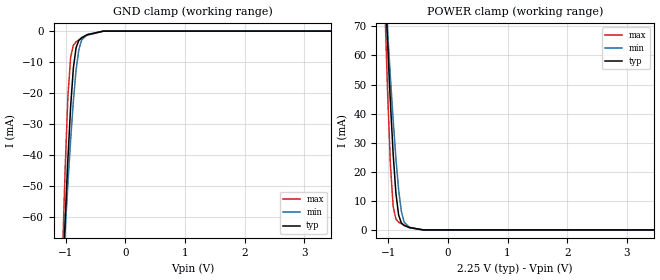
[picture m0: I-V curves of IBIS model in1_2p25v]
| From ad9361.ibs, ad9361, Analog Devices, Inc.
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|   Model: input1_2p25v
[Model]   in1_2p25v
Model_type Input
Vinl=0.45
Vinh=1.8
|   variable   typ   min   max
C_comp   4.040133E-14 3.086166E-14 4.264671E-13
[C Comp Corner]
C_comp   3.086166E-14 4.040133E-14 4.264671E-13
[Temperature Range]   25   85   -40
[Voltage Range]   2.25   2   2.625
[POWER Clamp Reference] 2.25   2   2.625
[GND Clamp Reference]   0   0   0
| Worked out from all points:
|   GND clamp passes 1 mA (typ) near -0.62 V on its own axis
|   POWER clamp passes 1 mA (typ) near -0.67 V on its own axis
[POWER_clamp]
| Voltage   I(typ)   I(min)   I(max)
-2.25V    724.8mA    552.8mA    1.029A
-1.056V   85.22mA    84.31mA    76.21mA
-1.01V    63.87mA    68.14mA    46.81mA
-964.3mV  43.91mA    52.59mA    22.58mA
-918.4mV  26.29mA    37.96mA    8.232mA
-872.4mV  12.74mA    24.76mA    3.764mA
-826.5mV  5.154mA    13.87mA    2.683mA
-780.6mV  2.422mA    6.432mA    2.159mA
-734.7mV  1.55mA     2.726mA    1.717mA
-642.9mV  800uA      772.2uA    924.6uA
-413.3mV  17.51uA    21.54uA    13.88uA
4.5V      -464.6pA   -5.157nA   -72.76pA
[GND_clamp]
| Voltage   I(typ)   I(min)   I(max)
-2.25V    -719.6mA   -548mA     -1.023A
-1.056V   -82.09mA   -80.71mA   -73.35mA
-1.01V    -61.01mA   -64.75mA   -44.48mA
-964.3mV  -41.45mA   -49.48mA   -21.31mA
-918.4mV  -24.46mA   -35.24mA   -8.43mA
-872.4mV  -11.91mA   -22.59mA   -4.569mA
-826.5mV  -5.331mA   -12.5mA    -3.5mA
-780.6mV  -2.988mA   -5.99mA    -2.883mA
-734.7mV  -2.126mA   -2.909mA   -2.337mA
-642.9mV  -1.198mA   -1.119mA   -1.341mA
-367.3mV  -9.539uA   -13.13uA   -5.263uA
4.5V      372pA      1.632nA    55.06pA
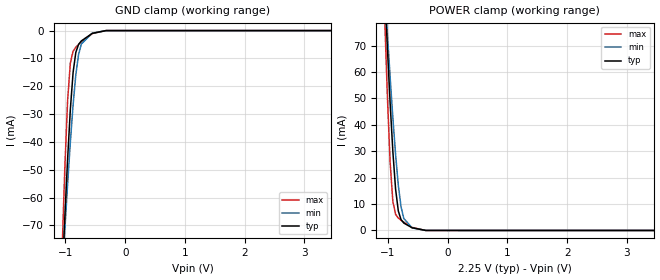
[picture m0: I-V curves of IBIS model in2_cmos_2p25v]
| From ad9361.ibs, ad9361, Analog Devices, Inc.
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|   Model: tx_input_2p25v
[Model]   in2_cmos_2p25v
Model_type Input
Vinl=0.375
Vinh=2.125
|   variable   typ   min   max
C_comp_power_clamp 9.285036E-13 8.725727E-13 1.103895E-12
C_comp_gnd_clamp   5.374554E-13 4.573817e-13 5.723049E-13
[C Comp Corner]
C_comp_power_clamp 9.285036E-13 1.103895E-12 8.725727E-13
C_comp_gnd_clamp   4.573817e-13 5.374554E-13 5.723049E-13
[Temperature Range]   25   85   -40
[Voltage Range]   2.25   2   2.625
[Power Clamp Reference]  2.25   2   2.625
[GND Clamp Reference]   0   0   0
[Pullup Reference]   2.25   2   2.625
[Pulldown Reference]   0   0   0
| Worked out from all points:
|   GND clamp passes 1 mA (typ) near -0.55 V on its own axis
|   POWER clamp passes 1 mA (typ) near -0.59 V on its own axis
[POWER_clamp]
| Voltage   I(typ)   I(min)   I(max)
-2.25V    758.5mA    585mA      1.064A
-1.056V   91.6mA     91.71mA    81.27mA
-1.01V    69.31mA    74.66mA    50.95mA
-964.3mV  48.45mA    58.25mA    25.93mA
-918.4mV  29.96mA    42.77mA    11mA
-872.4mV  15.62mA    28.75mA    6.12mA
-826.5mV  7.344mA    17.08mA    4.702mA
-780.6mV  4.069mA    8.909mA    3.864mA
-734.7mV  2.808mA    4.54mA     3.121mA
-596.9mV  1.035mA    991.2uA    1.17mA
-367.3mV  12.51uA    16.97uA    8.336uA
4.5V      -2.684nA   -19.17nA   -199.2pA
[GND_clamp]
| Voltage   I(typ)   I(min)   I(max)
-2.25V    -753.4mA   -580.1mA   -1.059A
-1.056V   -88.67mA   -88.22mA   -78.71mA
-1.01V    -66.66mA   -71.38mA   -48.96mA
-964.3mV  -46.19mA   -55.25mA   -25.09mA
-918.4mV  -28.35mA   -40.16mA   -11.69mA
-872.4mV  -15.03mA   -26.7mA    -7.416mA
-826.5mV  -7.805mA   -15.83mA   -5.976mA
-780.6mV  -4.962mA   -8.594mA   -5.001mA
-734.7mV  -3.72mA    -4.864mA   -4.107mA
-551mV    -1.001mA   -916.1uA   -1.063mA
-321.4mV  -5.147uA   -8.309uA   -2.147uA
4.5V      2.413nA    17.88nA    77.97pA
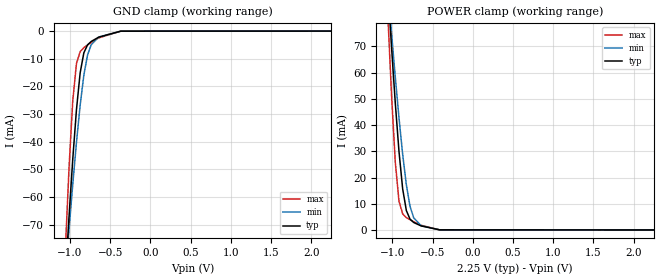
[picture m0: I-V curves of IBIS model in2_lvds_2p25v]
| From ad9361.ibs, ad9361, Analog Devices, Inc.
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|   Model: tx_input_2p25v
[Model]   in2_lvds_2p25v
Model_type Input
Vinl=0.375
Vinh=2.125
|   variable   typ   min   max
C_comp   5.374554E-13 4.573817e-13 5.723049E-13
[C Comp Corner]
C_comp   4.573817e-13 5.374554E-13 5.723049E-13
|C_comp_gnd_clamp 7.430165e-13 8.246844e-13 7.442808e-13
|C_comp_power_clamp 1.550972e-12 1.788704e-12 1.474126e-12
[Temperature Range]   25   85   -40
[Voltage Range]   2.25   2   2.625
[Power Clamp Reference]  2.25   2   2.625
[GND Clamp Reference]   0   0   0
[Pullup Reference]   2.25   2   2.625
[Pulldown Reference]   0   0   0
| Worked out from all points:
|   GND clamp passes 1 mA (typ) near -0.55 V on its own axis
|   POWER clamp passes 1 mA (typ) near -0.59 V on its own axis
[POWER_clamp]
| Voltage   I(typ)   I(min)   I(max)
-2.25V    758.6mA    585.1mA    1.064A
-1.056V   91.68mA    91.83mA    81.33mA
-1.01V    69.39mA    74.78mA    50.99mA
-964.3mV  48.52mA    58.36mA    25.97mA
-918.4mV  30.03mA    42.87mA    11.03mA
-872.4mV  15.67mA    28.85mA    6.146mA
-826.5mV  7.389mA    17.17mA    4.727mA
-780.6mV  4.105mA    8.984mA    3.889mA
-734.7mV  2.836mA    4.602mA    3.144mA
-642.9mV  1.544mA    1.62mA     1.781mA
-413.3mV  46.7uA     54.09uA    39.39uA
2.25V     -312.9pA   -1.046uA   -50.19pA
[GND_clamp]
| Voltage   I(typ)   I(min)   I(max)
-2.25V    -753.5mA   -580.2mA   -1.059A
-1.056V   -88.74mA   -88.33mA   -78.75mA
-1.01V    -66.72mA   -71.49mA   -48.99mA
-964.3mV  -46.25mA   -55.35mA   -25.11mA
-918.4mV  -28.4mA    -40.25mA   -11.71mA
-872.4mV  -15.08mA   -26.79mA   -7.437mA
-826.5mV  -7.843mA   -15.9mA    -5.998mA
-780.6mV  -4.993mA   -8.663mA   -5.023mA
-734.7mV  -3.748mA   -4.922mA   -4.129mA
-642.9mV  -2.214mA   -2.151mA   -2.472mA
-367.3mV  -25.76uA   -33.23uA   -15.79uA
2.25V     246.3pA    667.5nA    45.92pA
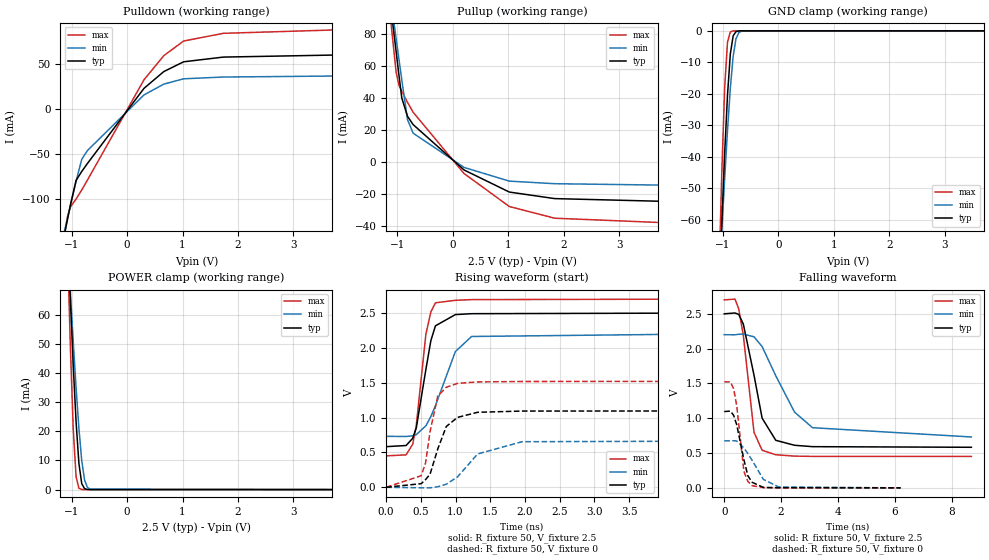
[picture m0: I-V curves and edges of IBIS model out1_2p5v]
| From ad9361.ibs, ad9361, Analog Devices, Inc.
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|   Model: output1_2p5v
[Model]   out1_2p5v
Model_type  3-state
Vref=0
Vmeas=1.125
Rref=1G
Cref=3pF
|variable   typ   min   max
C_comp_pullup   3.786304E-13 3.343610E-13 3.932215E-13
C_comp_pulldown   3.175618E-13 2.997974E-13 4.121601E-13
[C Comp Corner]
C_comp_pullup   3.343610E-13 3.932215E-13 3.786304E-13
C_comp_pulldown   2.997974E-13 4.121601E-13 3.175618E-13
[Temperature Range]   25   85   -40
[Voltage Range]   2.5   2.2   2.7
[Power Clamp Reference] 2.5   2.2   2.7
[GND Clamp Reference]   0   0   0
[Pullup Reference]   2.5   2.2   2.7
[Pulldown Reference]   0   0   0
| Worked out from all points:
|   slope of the pulldown table from 0 to 0.375 V, typ, clamps not added: 13.7 ohm
|   slope of the pullup table from 0 to 0.375 V, typ, clamps not added: 41.8 ohm
|   GND clamp passes 1 mA (typ) near -0.79 V on its own axis
|   POWER clamp passes 1 mA (typ) near -0.79 V on its own axis
|   rising waveform, R_fixture 50, V_fixture 2.5: 20-80 % time 186ps typ, 328ps min, 148ps max; typ from 0.583 V to 2.5 V
|   falling waveform, R_fixture 50, V_fixture 2.5: 20-80 % time 530ps typ, 1.11ns min, 365ps max; typ from 2.5 V to 0.583 V
|   rising waveform, R_fixture 50, V_fixture 0: 20-80 % time 226ps typ, 425ps min, 159ps max; typ from 0 V to 1.1 V
|   falling waveform, R_fixture 50, V_fixture 0: 20-80 % time 339ps typ, 598ps min, 246ps max; typ from 1.1 V to 0 V
[Power clamp]
| Voltage   I(typ)   I(min)   I(max)
-2.5V     835.1mA    627.7mA    1.205A
-1.071V   87.93mA    84.9mA     81.41mA
-1.02V    64.48mA    67.45mA    48.31mA
-969.4mV  42.54mA    50.69mA    20.66mA
-918.4mV  23.27mA    34.97mA    4.431mA
-867.3mV  8.965mA    20.98mA    449.5uA
-816.3mV  2.046mA    9.914mA    36.63uA
-765.3mV  322uA      3.267mA    2.917uA
-714.3mV  45.7uA     765.8uA    231.8nA
-663.3mV  6.378uA    153.6uA    18.42nA
5V        -10pA      -10.07pA   -10pA
[GND Clamp]
| Voltage   I(typ)   I(min)   I(max)
-2.5V     -829.5mA   -622.5mA   -1.199A
-1.071V   -83.56mA   -80.69mA   -77.03mA
-1.02V    -60.42mA   -63.43mA   -44.54mA
-969.4mV  -38.93mA   -46.93mA   -18.07mA
-918.4mV  -20.43mA   -31.61mA   -3.595mA
-867.3mV  -7.361mA   -18.23mA   -364.6uA
-816.3mV  -1.595mA   -8.11mA    -31.06uA
-765.3mV  -253.4uA   -2.511mA   -2.598uA
-714.3mV  -37.22uA   -578.3uA   -217nA
-663.3mV  -5.395uA   -118.2uA   -18.12nA
5V        10pA       9.933pA    10pA
[Pullup]
| Voltage   I(typ)   I(min)   I(max)
-2.5V     493.3mA    449.2mA    559.2mA
-1.122V   98.28mA    102.8mA    90.27mA
-1.071V   83.57mA    89.97mA    72.81mA
-1.02V    68.84mA    77.1mA     55.94mA
-969.4mV  54.11mA    64.2mA     47.85mA
-918.4mV  39.94mA    51.26mA    44.22mA
-816.3mV  28.52mA    26.5mA     37.24mA
-714.3mV  23.26mA    17.89mA    30.99mA
204.1mV   -5.177mA   -3.583mA   -7.408mA
1.02V     -19.01mA   -12.17mA   -28.07mA
1.837V    -23.11mA   -13.78mA   -35.39mA
5V        -25.88mA   -15.21mA   -39.9mA
[Pulldown]
| Voltage   I(typ)   I(min)   I(max)
-2.5V     -546.8mA   -489.9mA   -626.1mA
-1.122V   -138.1mA   -134.6mA   -137.9mA
-1.071V   -122.5mA   -121.1mA   -119.5mA
-1.02V    -106.9mA   -107.6mA   -109.2mA
-918.4mV  -79.64mA   -80.52mA   -100.4mA
-816.3mV  -69.62mA   -56.09mA   -90.25mA
-714.3mV  -60.77mA   -46.31mA   -79.29mA
306.1mV   23.11mA    15.79mA    32.66mA
663.3mV   41.82mA    27.81mA    59.6mA
1.02V     52.7mA     33.75mA    75.87mA
1.735V    57.95mA    35.71mA    84.45mA
5V        61.68mA    37.52mA    90.61mA
[Rising Waveform]
R_fixture = 50
V_fixture = 2.5
V_fixture_min = 2.2
V_fixture_max = 2.7
| time   V(typ)   V(min)   V(max)
0s        583mV      731.1mV    451.1mV
287.2ps   599.6mV    729mV      465.2mV
382ps     702.8mV    738.9mV    617.3mV
433.9ps   851.7mV    755.5mV    890.2mV
572.6ps   1.694V     882.9mV    2.199V
643.8ps   2.104V     1.015V     2.516V
710.1ps   2.317V     1.172V     2.647V
996.5ps   2.478V     1.947V     2.683V
1.231ns   2.491V     2.164V     2.693V
4.552ns   2.5V       2.2V       2.7V
[Falling Waveform]
R_fixture = 50
V_fixture = 2.5
V_fixture_min = 2.2
V_fixture_max = 2.7
| time   V(typ)   V(min)   V(max)
0s        2.5V       2.2V       2.7V
378ps     2.512V     2.199V     2.711V
510.3ps   2.492V     2.206V     2.571V
672.2ps   2.352V     2.209V     2.189V
1.048ns   1.617V     2.17V      797.2mV
1.333ns   1.001V     2.029V     539.6mV
1.813ns   682.9mV    1.61V      475.7mV
2.473ns   611.7mV    1.088V     455.9mV
3.105ns   591.8mV    864.1mV    451.9mV
8.693ns   582.9mV    731mV      451.1mV
[Rising Waveform]
R_fixture = 50
V_fixture = 0
V_fixture_min = 0
V_fixture_max = 0
| time   V(typ)   V(min)   V(max)
0s        19.37uV    15.21uV    23.25uV
504.8ps   52.06mV    -7.305mV   165.8mV
567.9ps   110.5mV    -8.171mV   350.6mV
632.5ps   188.6mV    -7.654mV   800.1mV
742.5ps   547.3mV    7.585mV    1.308V
865.9ps   872.2mV    44.05mV    1.435V
1.027ns   1.003V     148mV      1.491V
1.317ns   1.076V     478.2mV    1.512V
1.958ns   1.094V     654.1mV    1.518V
9.544ns   1.096V     674.9mV    1.523V
[Falling Waveform]
R_fixture = 50
V_fixture = 0
V_fixture_min = 0
V_fixture_max = 0
| time   V(typ)   V(min)   V(max)
0s        1.096V     674.9mV    1.523V
218.4ps   1.103V     675.9mV    1.523V
334.3ps   1.039V     677.5mV    1.42V
441.1ps   903.1mV    673mV      1.174V
692.4ps   404.6mV    572.7mV    237mV
831.1ps   173.9mV    492.8mV    93.71mV
982.1ps   80mV       395.5mV    31.05mV
1.375ns   5.95mV     122mV      4.401mV
1.912ns   1.701mV    13.25mV    958.5uV
6.204ns   -9.734uV   432.3nV    -2.344uV
[Ramp]
| variable   typ   min   max
dV/dt_r  0.657452/2.26E-10   0.404945/4.25E-10   0.913694/1.59E-10
dV/dt_f  1.150229/5.3E-10   0.881349/1.11E-09   1.349344/3.65E-10
R_load = 50
|   End of [Model]: output1_2p5v
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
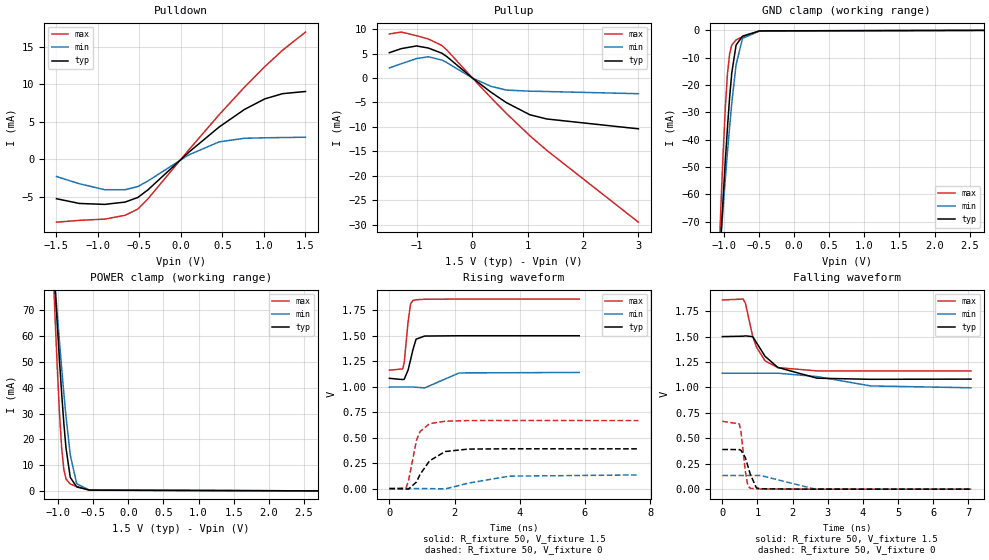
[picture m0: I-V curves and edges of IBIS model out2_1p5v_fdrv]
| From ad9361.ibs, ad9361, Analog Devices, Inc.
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|   Model: output1_1p5v_fdrv
[Model]   out2_1p5v_fdrv
Model_type  3-state
Vref=0
Vmeas=0.75
Rref=1G
Cref=3pF
|variable   typ   min   max
C_comp_pullup   2.194652E-14 1.815507E-14 2.472456E-13
C_comp_pulldown   7.095162E-14   7.061154E-14   9.191828E-14
[C Comp Corner]
C_comp_pullup   2.194652E-14 1.815507E-14 2.472456E-13
C_comp_pulldown   7.061154E-14  7.095162E-14   9.191828E-14
[Temperature Range]   25   85   -40
[Voltage Range]   1.5   1.14   1.86
[Power Clamp Reference] 1.5   1.14   1.86
[GND Clamp Reference]   0   0   0
[Pullup Reference]   1.5   1.14   1.86
[Pulldown Reference]   0   0   0
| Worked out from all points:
|   slope of the pulldown table from 0 to 0.225 V, typ, clamps not added: 102 ohm
|   slope of the pullup table from 0 to 0.225 V, typ, clamps not added: 114 ohm
|   GND clamp passes 1 mA (typ) near -0.62 V on its own axis
|   POWER clamp passes 1 mA (typ) near -0.67 V on its own axis
|   rising waveform, R_fixture 50, V_fixture 1.5: 20-80 % time 195ps typ, 390ps min, 134ps max; typ from 1.08 V to 1.5 V
|   falling waveform, R_fixture 50, V_fixture 1.5: 20-80 % time 739ps typ, 1.16ns min, 412ps max; typ from 1.5 V to 1.08 V
|   rising waveform, R_fixture 50, V_fixture 0: 20-80 % time 530ps typ, 1.06ns min, 295ps max; typ from 0 V to 0.39 V
|   falling waveform, R_fixture 50, V_fixture 0: 20-80 % time 202ps typ, 456ps min, 135ps max; typ from 0.39 V to 0 V
[Power clamp]
| Voltage   I(typ)   I(min)   I(max)
-1.5V     315.2mA    253.3mA    416.6mA
-1.071V   92.57mA    89.81mA    86.68mA
-1.041V   78mA       78.87mA    66.08mA
-1.01V    63.89mA    68.15mA    46.88mA
-979.6mV  50.39mA    57.71mA    29.94mA
-949mV    37.76mA    47.61mA    16.67mA
-918.4mV  26.36mA    37.99mA    8.422mA
-887.8mV  16.76mA    28.99mA    4.656mA
-826.5mV  5.248mA    13.94mA    2.684mA
-734.7mV  1.554mA    2.767mA    1.717mA
-551mV    302.9uA    280.6uA    313uA
3V        -277.9pA   -2.353nA   -34.9pA
[GND Clamp]
| Voltage   I(typ)   I(min)   I(max)
-1.5V     -310.6mA   -248.8mA   -412.2mA
-1.071V   -89.35mA   -86.15mA   -83.72mA
-1.041V   -74.95mA   -75.34mA   -63.36mA
-1.01V    -61.03mA   -64.76mA   -44.55mA
-979.6mV  -47.78mA   -54.49mA   -28.26mA
-949mV    -35.47mA   -44.62mA   -15.91mA
-918.4mV  -24.54mA   -35.26mA   -8.594mA
-887.8mV  -15.57mA   -26.62mA   -5.351mA
-826.5mV  -5.408mA   -12.57mA   -3.501mA
-734.7mV  -2.129mA   -2.939mA   -2.338mA
-489.8mV  -207.4uA   -201.8uA   -188.8uA
3V        251.7pA    4.602nA    34.07pA
[Pullup]
| Voltage   I(typ)   I(min)   I(max)
-1.5V     5.172mA    2.057mA    9mA
-1.286V   5.99mA     2.909mA    9.378mA
-1.01V    6.55mA     3.968mA    8.65mA
-795.9mV  6.117mA    4.337mA    7.962mA
-551mV    5.057mA    3.651mA    6.634mA
-459.2mV  4.342mA    3.119mA    5.685mA
0V        260.8nA    540.6nA    125.1nA
336.7mV   -2.914mA   -1.708mA   -4.047mA
612.2mV   -5.021mA   -2.471mA   -7.22mA
1.041V    -7.528mA   -2.695mA   -11.83mA
1.347V    -8.381mA   -2.767mA   -14.81mA
3V        -10.39mA   -3.213mA   -29.47mA
[Pulldown]
| Voltage   I(typ)   I(min)   I(max)
-1.5V     -5.271mA   -2.307mA   -8.404mA
-1.224V   -5.903mA   -3.272mA   -8.157mA
-918.4mV  -6.027mA   -4.068mA   -7.995mA
-673.5mV  -5.719mA   -4.067mA   -7.483mA
-520.4mV  -5.107mA   -3.65mA    -6.653mA
-398mV    -4.082mA   -2.898mA   -5.286mA
91.84mV   916.9uA    574.5uA    1.22mA
459.2mV   4.302mA    2.32mA     5.941mA
765.3mV   6.653mA    2.803mA    9.632mA
1.01V     8.063mA    2.868mA    12.37mA
1.224V    8.758mA    2.9mA      14.56mA
1.5V      9.049mA    2.936mA    16.98mA
[Rising Waveform]
R_fixture = 50
V_fixture = 1.5
V_fixture_min = 1.14
V_fixture_max = 1.86
| time   V(typ)   V(min)   V(max)
0s        1.082V     996.7mV    1.162V
409.4ps   1.07V      996.7mV    1.175V
452.3ps   1.072V     996.7mV    1.23V
574ps     1.163V     996.8mV    1.636V
650.7ps   1.265V     997mV      1.813V
723.4ps   1.364V     997.1mV    1.846V
818ps     1.466V     994.8mV    1.853V
1.079ns   1.497V     987.7mV    1.858V
2.144ns   1.5V       1.135V     1.86V
5.825ns   1.5V       1.14V      1.86V
[Falling Waveform]
R_fixture = 50
V_fixture = 1.5
V_fixture_min = 1.14
V_fixture_max = 1.86
| time   V(typ)   V(min)   V(max)
0s        1.5V       1.14V      1.86V
593.3ps   1.504V     1.14V      1.869V
657.5ps   1.507V     1.14V      1.828V
867ps     1.499V     1.14V      1.499V
974ps     1.44V      1.14V      1.397V
1.215ns   1.307V     1.14V      1.262V
1.58ns    1.197V     1.14V      1.195V
2.694ns   1.091V     1.107V     1.163V
4.219ns   1.08V      1.015V     1.162V
7.076ns   1.082V     996.8mV    1.162V
[Rising Waveform]
R_fixture = 50
V_fixture = 0
V_fixture_min = 0
V_fixture_max = 0
| time   V(typ)   V(min)   V(max)
0s        -1.048nV   8.167nV    -604.6pV
510.7ps   -3.493mV   1.253uV    7.752mV
582.4ps   -5.65mV    -5.414uV   71.56mV
832ps     64.81mV    94.02uV    474mV
940.3ps   138.5mV    197uV      559.7mV
1.233ns   272.3mV    -379.6uV   637.4mV
1.712ns   363.6mV    -3.085mV   661.2mV
2.417ns   387.8mV    53.18mV    667.5mV
3.683ns   390.5mV    122.2mV    667.8mV
7.642ns   390.1mV    134.2mV    667.4mV
[Falling Waveform]
R_fixture = 50
V_fixture = 0
V_fixture_min = 0
V_fixture_max = 0
| time   V(typ)   V(min)   V(max)
0s        390.1mV    134.2mV    667.5mV
485ps     389.2mV    134.2mV    641.6mV
532.9ps   381mV      134.2mV    559.8mV
654.5ps   311.1mV    134.2mV    176.6mV
726.9ps   228.1mV    134.2mV    34.37mV
797ps     145.7mV    134.2mV    8.667mV
969.8ps   13.38mV    134.2mV    3.326mV
1.089ns   3.278mV    134.8mV    1.45mV
2.606ns   70.89uV    3.36mV     15.67uV
7.084ns   175.1nV    1.547uV    1.93uV
[Ramp]
| variable   typ   min   max
dV/dt_r  0.250830/7.38E-10   0.086493/1.19E-10   0.418507/4.12E-10
dV/dt_f  0.234081/5.30E-10   0.080509/1.06E-10   0.400463/2.95E-10
R_load = 50
|   End of [Model]: output1_1p5v_fdrv
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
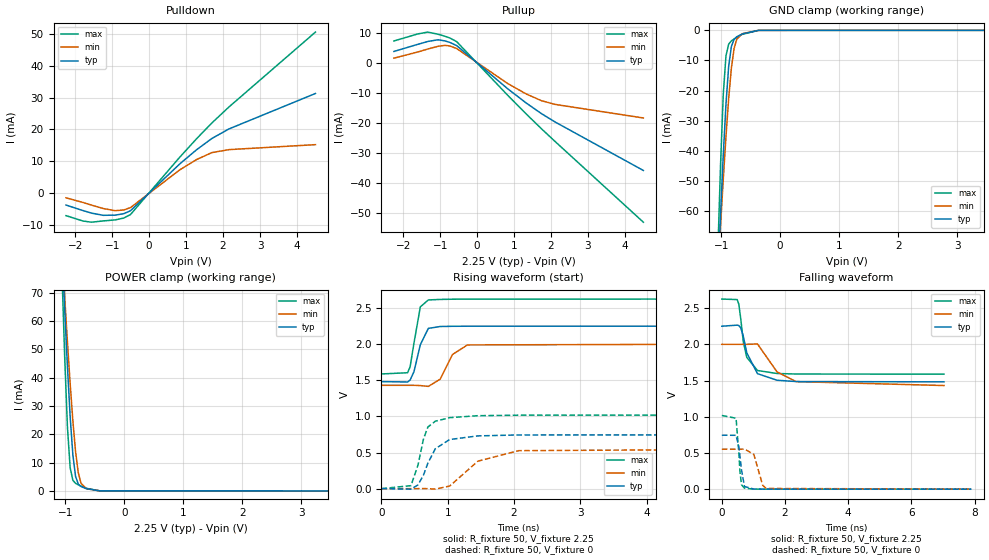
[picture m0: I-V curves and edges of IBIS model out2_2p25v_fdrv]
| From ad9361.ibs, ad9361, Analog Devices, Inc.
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|   Model: output1_2p25v_fdrv
[Model]   out2_2p25v_fdrv
Model_type  3-state
Vref=0
Vmeas=1.125
Rref=1G
Cref=3pF
|variable   typ   min   max
C_comp_pullup   3.897946E-14 8.455150E-15 2.538428E-13
C_comp_pulldown   9.928410E-14 9.028872E-14  1.727192E-13
[C Comp Corner]
C_comp_pullup   8.455150E-15 3.897946E-14 2.538428E-13
C_comp_pulldown   9.928410E-14  9.028872E-14 1.727192E-13
[Temperature Range]   25   85   -40
[Voltage Range]   2.25   2   2.625
[Power Clamp Reference]  2.25   2   2.625
[GND Clamp Reference]   0   0   0
[Pullup Reference]   2.25   2   2.625
[Pulldown Reference]   0   0   0
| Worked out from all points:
|   slope of the pulldown table from 0 to 0.337 V, typ, clamps not added: 88 ohm
|   slope of the pullup table from 0 to 0.337 V, typ, clamps not added: 93.9 ohm
|   GND clamp passes 1 mA (typ) near -0.62 V on its own axis
|   POWER clamp passes 1 mA (typ) near -0.67 V on its own axis
|   rising waveform, R_fixture 50, V_fixture 2.25: 20-80 % time 119ps typ, 198ps min, 110ps max; typ from 1.48 V to 2.25 V
|   falling waveform, R_fixture 50, V_fixture 2.25: 20-80 % time 357ps typ, 679ps min, 227ps max; typ from 2.25 V to 1.48 V
|   rising waveform, R_fixture 50, V_fixture 0: 20-80 % time 245ps typ, 476ps min, 167ps max; typ from 0 V to 0.745 V
|   falling waveform, R_fixture 50, V_fixture 0: 20-80 % time 118ps typ, 212ps min, 92.3ps max; typ from 0.745 V to 0 V
[Power clamp]
| Voltage   I(typ)   I(min)   I(max)
-2.25V    724.8mA    552.8mA    1.029A
-1.056V   85.22mA    84.31mA    76.21mA
-1.01V    63.87mA    68.14mA    46.81mA
-964.3mV  43.91mA    52.59mA    22.58mA
-918.4mV  26.29mA    37.96mA    8.232mA
-872.4mV  12.74mA    24.76mA    3.764mA
-826.5mV  5.154mA    13.87mA    2.683mA
-780.6mV  2.422mA    6.432mA    2.159mA
-734.7mV  1.55mA     2.726mA    1.717mA
-642.9mV  800uA      772.2uA    924.6uA
-413.3mV  17.51uA    21.54uA    13.88uA
4.5V      -464.6pA   -5.157nA   -72.76pA
[GND Clamp]
| Voltage   I(typ)   I(min)   I(max)
-2.25V    -719.6mA   -548mA     -1.023A
-1.056V   -82.09mA   -80.71mA   -73.35mA
-1.01V    -61.01mA   -64.75mA   -44.48mA
-964.3mV  -41.45mA   -49.48mA   -21.31mA
-918.4mV  -24.46mA   -35.24mA   -8.43mA
-872.4mV  -11.91mA   -22.59mA   -4.569mA
-826.5mV  -5.331mA   -12.5mA    -3.5mA
-780.6mV  -2.988mA   -5.99mA    -2.883mA
-734.7mV  -2.126mA   -2.909mA   -2.337mA
-642.9mV  -1.198mA   -1.119mA   -1.341mA
-367.3mV  -9.539uA   -13.13uA   -5.263uA
4.5V      372pA      1.632nA    55.06pA
[Pullup]
| Voltage   I(typ)   I(min)   I(max)
-2.25V    3.851mA    1.612mA    7.34mA
-1.607V   6.212mA    3.658mA    9.69mA
-1.332V   7.182mA    4.662mA    10.31mA
-1.056V   7.739mA    5.563mA    9.593mA
-872.4mV  7.384mA    5.88mA     8.936mA
-734.7mV  6.851mA    5.68mA     8.325mA
-551mV    5.811mA    4.813mA    7.12mA
826.5mV   -8.58mA    -6.839mA   -10.74mA
1.332V    -13.37mA   -10.35mA   -17.03mA
1.745V    -16.92mA   -12.59mA   -21.98mA
2.112V    -19.69mA   -13.82mA   -26.2mA
4.5V      -35.86mA   -18.35mA   -53.12mA
[Pulldown]
| Voltage   I(typ)   I(min)   I(max)
-2.25V    -3.829mA   -1.549mA   -7.157mA
-1.791V   -5.567mA   -3.018mA   -8.856mA
-1.561V   -6.363mA   -3.838mA   -9.223mA
-1.24V    -7.063mA   -4.932mA   -8.817mA
-918.4mV  -7.002mA   -5.597mA   -8.502mA
-688.8mV  -6.544mA   -5.384mA   -7.927mA
-505.1mV  -5.626mA   -4.635mA   -6.816mA
826.5mV   9.098mA    7.231mA    11.21mA
1.286V    13.6mA     10.51mA    17.07mA
1.699V    17.13mA    12.68mA    22.02mA
2.158V    20.12mA    13.61mA    27.02mA
4.5V      31.28mA    15.18mA    50.6mA
[Rising Waveform]
R_fixture = 50
V_fixture = 2.25
V_fixture_min = 2
V_fixture_max = 2.625
| time   V(typ)   V(min)   V(max)
0s        1.482V     1.431V     1.588V
394.8ps   1.477V     1.431V     1.605V
432.5ps   1.503V     1.431V     1.687V
490.9ps   1.62V      1.431V     2.016V
586.7ps   1.993V     1.427V     2.517V
707.5ps   2.219V     1.416V     2.613V
886.7ps   2.245V     1.516V     2.62V
1.071ns   2.248V     1.857V     2.623V
1.298ns   2.249V     1.99V      2.624V
5.42ns    2.25V      2V         2.625V
[Falling Waveform]
R_fixture = 50
V_fixture = 2.25
V_fixture_min = 2
V_fixture_max = 2.625
| time   V(typ)   V(min)   V(max)
0s        2.25V      2V         2.625V
487.6ps   2.265V     2V         2.618V
537.1ps   2.26V      2V         2.555V
598.8ps   2.227V     2V         2.353V
677.3ps   2.117V     2V         2.043V
790ps     1.882V     2V         1.819V
1.128ns   1.595V     2.005V     1.639V
1.748ns   1.504V     1.619V     1.597V
2.354ns   1.486V     1.485V     1.59V
7.032ns   1.482V     1.431V     1.588V
[Rising Waveform]
R_fixture = 50
V_fixture = 0
V_fixture_min = 0
V_fixture_max = 0
| time   V(typ)   V(min)   V(max)
0s        5.546nV    13.23nV    401.8pV
445.9ps   -7.354mV   -6.643uV   41.46mV
552.6ps   52.91mV    230.8uV    331mV
633.8ps   186.9mV    854.3uV    686.3mV
700.5ps   352.1mV    -228.4uV   852.8mV
812.4ps   552.2mV    -6.785mV   933.7mV
1.03ns    680.2mV    36.01mV    982.7mV
1.455ns   730.3mV    380.3mV    1.01V
2.07ns    743.4mV    525.9mV    1.017V
7.41ns    745.2mV    552.4mV    1.018V
[Falling Waveform]
R_fixture = 50
V_fixture = 0
V_fixture_min = 0
V_fixture_max = 0
| time   V(typ)   V(min)   V(max)
0s        745.2mV    552.4mV    1.018V
450ps     743.9mV    552.4mV    979mV
539.9ps   585.2mV    552.4mV    490.9mV
573.9ps   451.7mV    552.4mV    240.4mV
622.3ps   267.2mV    552.6mV    63.25mV
716.3ps   37.08mV    553mV      13.03mV
1.011ns   2.028mV    481.8mV    1.886mV
1.295ns   550.5uV    52.29mV    496.3uV
1.404ns   453.6uV    9.793mV    377.5uV
7.896ns   2.329uV    -264.5nV   2.537uV
[Ramp]
| variable   typ   min   max
dV/dt_r  0.447117/2.45E-10   0.331433/4.76E-10   0.610619/1.67E-10
dV/dt_f  0.460633/3.57E-10   0.341495/6.78E-10   0.621916/2.27E-10
R_load = 50
|   End of [Model]: output1_2p25v_fdrv
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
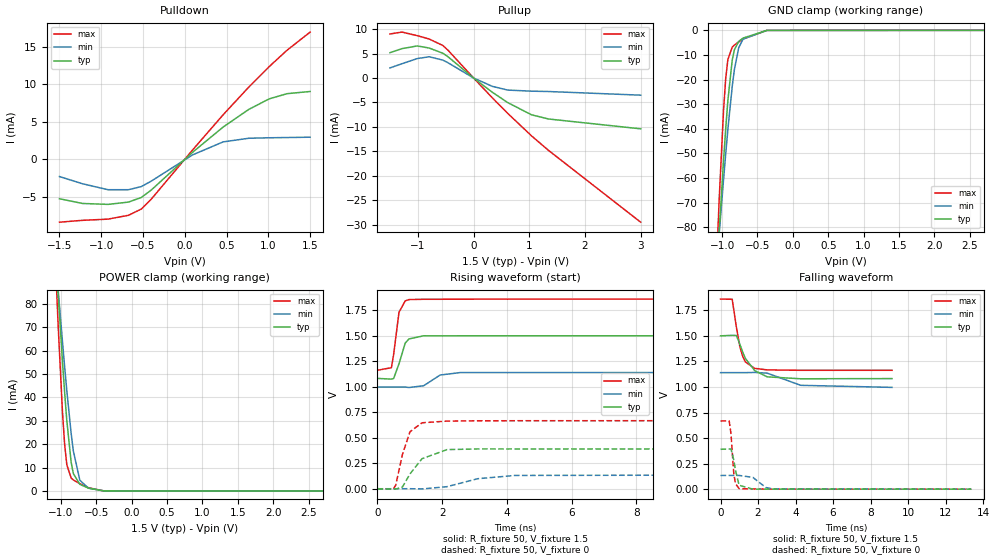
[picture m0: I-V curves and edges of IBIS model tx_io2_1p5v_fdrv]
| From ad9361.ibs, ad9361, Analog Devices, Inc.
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|   Model: SCKI_io_1p5v_fdrv
[Model]   tx_io2_1p5v_fdrv
Model_type  I/O
Vinl=0.3
Vinh=1.2
Vref=0
Vmeas=0.75
Rref=1G
Cref=3pF
|variable   typ   min   max
C_comp_pullup   1.044441E-12  9.208270E-13  1.087595E-12
C_comp_pulldown   5.614944E-13  5.476631E-13  6.362382E-13
[C Comp Corner]
C_comp_pullup   9.208270E-13  1.087595E-12 1.044441E-12
C_comp_pulldown   5.476631E-13  6.362382E-13 5.614944E-13
[Temperature Range]   25   85   -40
[Voltage Range]   1.5   1.14   1.86
[Power Clamp Reference] 1.5   1.14   1.86
[GND Clamp Reference]   0   0   0
[Pullup Reference]   1.5   1.14   1.86
[Pulldown Reference]   0   0   0
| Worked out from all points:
|   slope of the pulldown table from 0 to 0.225 V, typ, clamps not added: 102 ohm
|   slope of the pullup table from 0 to 0.225 V, typ, clamps not added: 114 ohm
|   GND clamp passes 1 mA (typ) near -0.55 V on its own axis
|   POWER clamp passes 1 mA (typ) near -0.59 V on its own axis
|   rising waveform, R_fixture 50, V_fixture 1.5: 20-80 % time 233ps typ, 424ps min, 166ps max; typ from 1.08 V to 1.5 V
|   falling waveform, R_fixture 50, V_fixture 1.5: 20-80 % time 743ps typ, 1.25ns min, 438ps max; typ from 1.5 V to 1.08 V
|   rising waveform, R_fixture 50, V_fixture 0: 20-80 % time 558ps typ, 1.11ns min, 340ps max; typ from 0 V to 0.39 V
|   falling waveform, R_fixture 50, V_fixture 0: 20-80 % time 237ps typ, 557ps min, 164ps max; typ from 0.39 V to 0 V
[Power clamp]
| Voltage   I(typ)   I(min)   I(max)
-1.5V     331.3mA    269.7mA    432.3mA
-1.071V   99.26mA    97.51mA    92.08mA
-1.041V   84.06mA    85.98mA    70.82mA
-979.6mV  55.23mA    63.64mA    33.54mA
-949mV    42mA       52.98mA    19.81mA
-918.4mV  30.03mA    42.8mA     11.19mA
-857.1mV  12.27mA    24.6mA     5.503mA
-826.5mV  7.441mA    17.15mA    4.703mA
-734.7mV  2.813mA    4.584mA    3.121mA
-612.2mV  1.192mA    1.167mA    1.361mA
-398mV    30.62uA    37uA       24.37uA
3V        -1.479nA   -13.11nA   -49.44pA
[GND Clamp]
| Voltage   I(typ)   I(min)   I(max)
-1.5V     -326.9mA   -265.3mA   -428.3mA
-1.071V   -96.26mA   -93.95mA   -89.41mA
-1.041V   -81.22mA   -82.55mA   -68.41mA
-979.6mV  -52.82mA   -60.55mA   -32.25mA
-949mV    -39.93mA   -50.1mA    -19.49mA
-918.4mV  -28.43mA   -40.19mA   -11.85mA
-857.1mV  -12.07mA   -22.79mA   -6.821mA
-826.5mV  -7.885mA   -15.9mA    -5.978mA
-765.3mV  -4.469mA   -7.087mA   -4.699mA
-704.1mV  -3.151mA   -3.577mA   -3.535mA
-367.3mV  -23.96uA   -30.7uA    -14.78uA
3V        1.335nA    12.82nA    47.92pA
[Pullup]
| Voltage   I(typ)   I(min)   I(max)
-1.5V     5.172mA    2.057mA    8.999mA
-1.286V   5.99mA     2.908mA    9.378mA
-1.01V    6.55mA     3.968mA    8.65mA
-795.9mV  6.117mA    4.337mA    7.962mA
-551mV    5.057mA    3.651mA    6.634mA
-459.2mV  4.342mA    3.119mA    5.685mA
0V        260.8nA    540.6nA    125.1nA
336.7mV   -2.914mA   -1.708mA   -4.047mA
612.2mV   -5.021mA   -2.471mA   -7.22mA
1.041V    -7.528mA   -2.695mA   -11.83mA
1.347V    -8.381mA   -2.767mA   -14.81mA
3V        -10.39mA   -3.511mA   -29.47mA
[Pulldown]
| Voltage   I(typ)   I(min)   I(max)
-1.5V     -5.271mA   -2.307mA   -8.404mA
-1.224V   -5.903mA   -3.272mA   -8.157mA
-918.4mV  -6.027mA   -4.068mA   -7.995mA
-673.5mV  -5.719mA   -4.067mA   -7.483mA
-520.4mV  -5.107mA   -3.65mA    -6.653mA
-398mV    -4.082mA   -2.898mA   -5.286mA
91.84mV   916.9uA    574.5uA    1.22mA
459.2mV   4.302mA    2.32mA     5.941mA
765.3mV   6.653mA    2.803mA    9.632mA
1.01V     8.063mA    2.868mA    12.37mA
1.224V    8.758mA    2.9mA      14.56mA
1.5V      9.049mA    2.944mA    16.98mA
[Rising Waveform]
R_fixture = 50
V_fixture = 1.5
V_fixture_min = 1.14
V_fixture_max = 1.86
| time   V(typ)   V(min)   V(max)
0s        1.082V     996.7mV    1.162V
432.4ps   1.075V     996.7mV    1.187V
500.1ps   1.081V     996.7mV    1.315V
666ps     1.225V     996.9mV    1.73V
858.1ps   1.428V     997.1mV    1.842V
974.8ps   1.469V     992.5mV    1.855V
1.429ns   1.5V       1.01V      1.858V
1.938ns   1.499V     1.115V     1.858V
2.558ns   1.5V       1.139V     1.859V
13.79ns   1.5V       1.14V      1.86V
[Falling Waveform]
R_fixture = 50
V_fixture = 1.5
V_fixture_min = 1.14
V_fixture_max = 1.86
| time   V(typ)   V(min)   V(max)
0s        1.5V       1.14V      1.86V
622.9ps   1.505V     1.14V      1.858V
843.1ps   1.504V     1.14V      1.589V
1.024ns   1.423V     1.14V      1.401V
1.162ns   1.351V     1.14V      1.31V
1.323ns   1.28V      1.14V      1.245V
1.823ns   1.16V      1.142V     1.182V
2.49ns    1.099V     1.135V     1.167V
4.277ns   1.08V      1.016V     1.163V
9.146ns   1.082V     995.9mV    1.163V
[Rising Waveform]
R_fixture = 50
V_fixture = 0
V_fixture_min = 0
V_fixture_max = 0
| time   V(typ)   V(min)   V(max)
0s        6.362nV    22.78nV    3.796nV
488.7ps   -1.911mV   1.235uV    -3.185mV
565.3ps   -4.171mV   552.7nV    34.78mV
771.6ps   16.7mV     -24.81uV   335mV
1.006ns   145.2mV    396.5uV    559.2mV
1.379ns   294.8mV    -1.702mV   646.7mV
2.152ns   383.8mV    20.3mV     663.3mV
3.1ns     390.4mV    98.4mV     666.4mV
4.263ns   390.2mV    130.6mV    666.8mV
12.35ns   390mV      134.2mV    667.3mV
[Falling Waveform]
R_fixture = 50
V_fixture = 0
V_fixture_min = 0
V_fixture_max = 0
| time   V(typ)   V(min)   V(max)
0s        390.1mV    134.2mV    667.5mV
462.4ps   393.3mV    134.2mV    666.8mV
556.3ps   392.7mV    134.2mV    545.8mV
709.6ps   284.2mV    134.2mV    149.2mV
799.7ps   184.2mV    134.3mV    53.83mV
989.8ps   38.33mV    134.4mV    5.372mV
1.723ns   334uV      115.2mV    2.184mV
2.421ns   617.4uV    15.59mV    1.336mV
2.793ns   501uV      2.968mV    1.099mV
13.37ns   40.64uV    43.62uV    94.64uV
[Ramp]
| variable   typ   min   max
dV/dt_r  0.234020/5.58E-10   0.080540/1.11E-9   0.400437/3.40E-10
dV/dt_f  0.250639/7.42E-10   0.086203/1.24E-9   0.418441/4.38E-10
R_load = 50
|   End of [Model]: 1p5v_fdrv
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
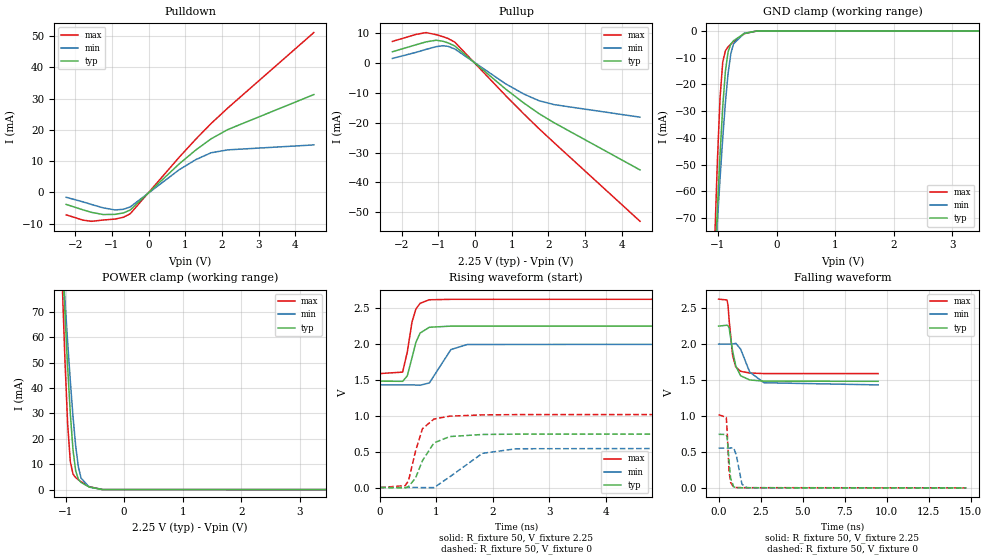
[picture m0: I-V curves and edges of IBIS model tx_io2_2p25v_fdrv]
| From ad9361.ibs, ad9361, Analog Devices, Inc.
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|   Model: SCKI_io2_2p25v_fdrv
[Model]   tx_io2_2p25v_fdrv
Model_type  I/O
Vinl=0.45
Vinh=1.8
Vref=0
Vmeas=1.125
Rref=1G
Cref=3pF
|variable   typ   min   max
C_comp_pullup   1.098879E-12 9.367522E-13 1.183790E-12
C_comp_pulldown   5.121521E-13 4.155030E-13 5.874892E-13
[C Comp Corner]
C_comp_pullup   9.367522E-13 1.098879E-12 1.183790E-12
C_comp_pulldown   5.121521E-13 5.874892E-13 4.155030E-13
[Temperature Range]   25   85   -40
[Voltage Range]   2.25   2   2.625
[Power Clamp Reference]  2.25   2   2.625
[GND Clamp Reference]   0   0   0
[Pullup Reference]   2.25   2   2.625
[Pulldown Reference]   0   0   0
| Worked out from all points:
|   slope of the pulldown table from 0 to 0.337 V, typ, clamps not added: 88 ohm
|   slope of the pullup table from 0 to 0.337 V, typ, clamps not added: 93.9 ohm
|   GND clamp passes 1 mA (typ) near -0.55 V on its own axis
|   POWER clamp passes 1 mA (typ) near -0.59 V on its own axis
|   rising waveform, R_fixture 50, V_fixture 2.25: 20-80 % time 168ps typ, 260ps min, 145ps max; typ from 1.48 V to 2.25 V
|   falling waveform, R_fixture 50, V_fixture 2.25: 20-80 % time 398ps typ, 702ps min, 274ps max; typ from 2.25 V to 1.48 V
|   rising waveform, R_fixture 50, V_fixture 0: 20-80 % time 289ps typ, 524ps min, 210ps max; typ from 0 V to 0.745 V
|   falling waveform, R_fixture 50, V_fixture 0: 20-80 % time 153ps typ, 250ps min, 129ps max; typ from 0.745 V to 0 V
[Power clamp]
| Voltage   I(typ)   I(min)   I(max)
-2.25V    758.5mA    585mA      1.064A
-1.056V   91.6mA     91.71mA    81.27mA
-1.01V    69.31mA    74.66mA    50.95mA
-964.3mV  48.45mA    58.25mA    25.93mA
-918.4mV  29.96mA    42.77mA    11mA
-872.4mV  15.62mA    28.75mA    6.12mA
-826.5mV  7.344mA    17.08mA    4.702mA
-780.6mV  4.069mA    8.909mA    3.864mA
-734.7mV  2.808mA    4.54mA     3.121mA
-596.9mV  1.035mA    991.2uA    1.17mA
-367.3mV  12.51uA    16.97uA    8.336uA
4.5V      -2.684nA   -11.21nA   -171.1pA
[GND Clamp]
| Voltage   I(typ)   I(min)   I(max)
-2.25V    -753.4mA   -580.1mA   -1.059A
-1.056V   -88.67mA   -88.22mA   -78.71mA
-1.01V    -66.66mA   -71.38mA   -48.96mA
-964.3mV  -46.19mA   -55.25mA   -25.09mA
-918.4mV  -28.35mA   -40.16mA   -11.69mA
-872.4mV  -15.03mA   -26.7mA    -7.416mA
-826.5mV  -7.805mA   -15.83mA   -5.976mA
-780.6mV  -4.962mA   -8.594mA   -5.001mA
-734.7mV  -3.72mA    -4.864mA   -4.107mA
-551mV    -1.001mA   -916.1uA   -1.063mA
-321.4mV  -5.147uA   -8.309uA   -2.147uA
4.5V      2.413nA    17.88nA    17.88nA
[Pullup]
| Voltage   I(typ)   I(min)   I(max)
-2.25V    3.851mA    1.612mA    7.34mA
-1.607V   6.212mA    3.658mA    9.69mA
-1.332V   7.182mA    4.662mA    10.31mA
-1.056V   7.739mA    5.563mA    9.593mA
-872.4mV  7.384mA    5.88mA     8.936mA
-734.7mV  6.851mA    5.68mA     8.325mA
-551mV    5.811mA    4.813mA    7.12mA
826.5mV   -8.58mA    -6.839mA   -10.74mA
1.332V    -13.37mA   -10.35mA   -17.03mA
1.745V    -16.92mA   -12.59mA   -21.98mA
2.158V    -20mA      -13.91mA   -26.71mA
4.5V      -35.86mA   -18.12mA   -53.12mA
[Pulldown]
| Voltage   I(typ)   I(min)   I(max)
-2.25V    -3.829mA   -1.549mA   -7.157mA
-1.791V   -5.567mA   -3.018mA   -8.856mA
-1.561V   -6.363mA   -3.838mA   -9.223mA
-1.24V    -7.063mA   -4.932mA   -8.817mA
-918.4mV  -7.002mA   -5.597mA   -8.502mA
-688.8mV  -6.544mA   -5.384mA   -7.927mA
-505.1mV  -5.626mA   -4.635mA   -6.816mA
826.5mV   9.098mA    7.231mA    11.21mA
1.286V    13.6mA     10.51mA    17.07mA
1.699V    17.13mA    12.68mA    22.02mA
2.158V    20.12mA    13.61mA    27.02mA
4.5V      31.28mA    15.19mA    51.1mA
[Rising Waveform]
R_fixture = 50
V_fixture = 2.25
V_fixture_min = 2
V_fixture_max = 2.625
| time   V(typ)   V(min)   V(max)
0s        1.482V     1.431V     1.588V
399.9ps   1.48V      1.431V     1.608V
482.1ps   1.555V     1.431V     1.885V
566.4ps   1.809V     1.431V     2.306V
634.3ps   2.021V     1.428V     2.486V
709.9ps   2.153V     1.425V     2.567V
873.3ps   2.233V     1.457V     2.616V
1.256ns   2.249V     1.923V     2.622V
1.547ns   2.249V     1.993V     2.622V
15.55ns   2.25V      2V         2.625V
[Falling Waveform]
R_fixture = 50
V_fixture = 2.25
V_fixture_min = 2
V_fixture_max = 2.625
| time   V(typ)   V(min)   V(max)
0s        2.25V      2V         2.625V
499.1ps   2.262V     2V         2.613V
555.4ps   2.256V     2V         2.547V
628.5ps   2.22V      2V         2.325V
832.9ps   1.902V     2V         1.842V
1.022ns   1.694V     2.01V      1.68V
1.309ns   1.559V     1.93V      1.621V
1.848ns   1.501V     1.611V     1.597V
2.7ns     1.484V     1.462V     1.59V
9.489ns   1.482V     1.432V     1.589V
[Rising Waveform]
R_fixture = 50
V_fixture = 0
V_fixture_min = 0
V_fixture_max = 0
| time   V(typ)   V(min)   V(max)
0s        -9.416nV   41.34nV    -655.8pV
446.5ps   -4.501mV   -505.7nV   26.52mV
505.5ps   12.85mV    -4.657uV   98.4mV
629.5ps   133.2mV    418.9uV    510mV
751.7ps   374.7mV    -1.104mV   820.2mV
955.5ps   622.5mV    -1.277mV   954.4mV
1.233ns   709.9mV    148.3mV    994.5mV
1.812ns   739.4mV    476.3mV    1.012V
2.412ns   744.1mV    540.3mV    1.016V
12.16ns   745.1mV    552.2mV    1.018V
[Falling Waveform]
R_fixture = 50
V_fixture = 0
V_fixture_min = 0
V_fixture_max = 0
| time   V(typ)   V(min)   V(max)
0s        745.2mV    552.4mV    1.018V
456.4ps   742.2mV    552.4mV    979.9mV
510.8ps   693.4mV    552.4mV    776.2mV
619.7ps   378.3mV    552.9mV    232.3mV
710.8ps   134mV      554.5mV    76.96mV
898.5ps   13.53mV    554.5mV    7.705mV
1.053ns   1.442mV    454mV      4.078mV
1.389ns   1.341mV    49.67mV    3.255mV
1.69ns    1.372mV    1.747mV    2.76mV
14.73ns   30.88uV    120uV      33.94uV
[Ramp]
| variable   typ   min   max
dV/dt_r  0.447105/2.9E-10   0.331335/5.24E-10   0.610635/2.10E-10
dV/dt_f  0.460560/3.98E-10   0.341087/7.02E-10   0.621858/2.74E-10
R_load = 50
|   End of [Model]: SCKI_io2_2p25v_fdrv
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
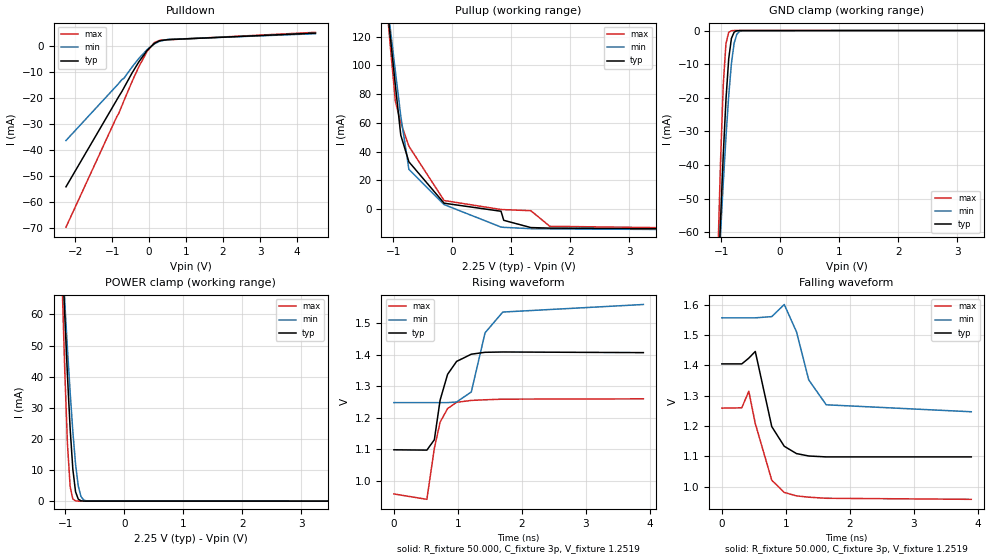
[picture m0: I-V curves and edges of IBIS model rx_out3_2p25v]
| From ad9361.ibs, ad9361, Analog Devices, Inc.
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|   Model: out3_300mV_2p25v
[Model]   rx_out3_2p25v
Model_type  3-state
Vref=1.2519
Vmeas=1.2519
Rref=50
Cref=3p
|variable   typ   min   max
C_comp_pullup   1.615894E-13 1.414284E-13 2.137635E-13
C_comp_pulldown   1.171761E-13 0.921963E-13 1.211097E-13
[C Comp Corner]
C_comp_pullup   1.615894E-13 1.414284E-13 2.137635E-13
C_comp_pulldown   1.171761E-13 0.921963E-13 1.211097E-13
[Temperature Range]   25   85   -40
[Voltage Range]   2.25   2   2.625
[Power Clamp Reference]  2.25   2   2.625
[GND Clamp Reference]   0   0   0
[Pullup Reference]   2.25   2   2.625
[Pulldown Reference]   0   0   0
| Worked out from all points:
|   slope of the pulldown table from 0 to 0.337 V, typ, clamps not added: 110 ohm
|   slope of the pullup table from 0 to 0.337 V, typ, clamps not added: 184 ohm
|   GND clamp passes 1 mA (typ) near -0.79 V on its own axis
|   POWER clamp passes 1 mA (typ) near -0.79 V on its own axis
|   rising waveform, R_fixture 50.000, C_fixture 3p, V_fixture 1.2519: 20-80 % time 204ps typ, 252ps min, 169ps max; typ from 1.1 V to 1.41 V
|   falling waveform, R_fixture 50.000, C_fixture 3p, V_fixture 1.2519: 20-80 % time 240ps typ, 270ps min, 258ps max; typ from 1.41 V to 1.1 V
[Power clamp]
|| Voltage   I(typ)   I(min)   I(max)
-2.25V    701.3mA    530.5mA    1.004A
-1.056V   80.79mA    79.61mA    71.14mA
-1.01V    59.97mA    64.04mA    42.24mA
-964.3mV  40.49mA    49.07mA    18.52mA
-918.4mV  23.31mA    34.99mA    4.668mA
-872.4mV  10.18mA    22.3mA     686.1uA
-826.5mV  2.988mA    11.86mA    77.11uA
-780.6mV  630.5uA    4.831mA    8.032uA
-734.7mV  113.7uA    1.474mA    827.9nA
-688.8mV  19.57uA    372.4uA    85.23nA
-642.9mV  3.334uA    86.79uA    8.774nA
4.5V      -9pA       -9.068pA   -9pA
[GND Clamp]
|| Voltage   I(typ)   I(min)   I(max)
-2.25V    -695.7mA   -525.3mA   -997.9mA
-1.056V   -76.5mA    -75.45mA   -66.91mA
-1.01V    -55.97mA   -60.07mA   -38.66mA
-964.3mV  -36.95mA   -45.35mA   -16.1mA
-918.4mV  -20.48mA   -31.63mA   -3.826mA
-872.4mV  -8.443mA   -19.48mA   -555.6uA
-826.5mV  -2.359mA   -9.854mA   -64.06uA
-780.6mV  -493.2uA   -3.788mA   -6.958uA
-734.7mV  -90.82uA   -1.119mA   -749.6nA
-688.8mV  -16.13uA   -283.1uA   -80.68nA
-642.9mV  -2.844uA   -67.34uA   -8.683nA
4.5V      9pA        9.079pA    9pA
[Pullup]
| OG Voltage   I(typ)   I(min)   I(max)
-2.25V    637.1mA    580.6mA    725.8mA
-1.102V   140.9mA    144mA      138.6mA
-1.056V   122.6mA    127.8mA    116.4mA
-964.3mV  86.32mA    96.06mA    75.12mA
-872.4mV  51.46mA    64.84mA    60.02mA
-734.7mV  32.93mA    27.69mA    43.79mA
-137.8mV  4.103mA    3.14mA     5.979mA
826.5mV   -1.488mA   -12.49mA   -289.2uA
872.4mV   -7.795mA   -12.7mA    -363uA
1.332V    -12.86mA   -13.62mA   -1.092mA
1.653V    -13.23mA   -13.77mA   -11.97mA
4.5V      -13.85mA   -14.35mA   -13.42mA
[Pulldown]
| Voltage   I(typ)   I(min)   I(max)
-2.25V    -54.28mA   -36.41mA   -69.86mA
-872.4mV  -20.67mA   -15.15mA   -27.12mA
-826.5mV  -19.55mA   -14.44mA   -26.09mA
-734.7mV  -17.43mA   -12.86mA   -22.91mA
-688.8mV  -16.23mA   -12.52mA   -21.29mA
-459.2mV  -10.27mA   -8.006mA   -13.55mA
-275.5mV  -5.994mA   -4.676mA   -7.846mA
-45.92mV  -1.503mA   -1.211mA   -1.79mA
137.8mV   1.008mA    819.1uA    1.334mA
275.5mV   2.086mA    1.86mA     2.21mA
505.1mV   2.513mA    2.6mA      2.466mA
4.5V      5.029mA    4.805mA    5.337mA
[Rising Waveform]
R_fixture = 50.000
C_fixture = 3p
V_fixture = 1.2519
V_fixture_min = 1.4025
V_fixture_max = 1.1081
|  time   V(typ)   V(min)   V(max)
0s        1.098V     1.248V     957.6mV
515.3ps   1.097V     1.248V     940.5mV
632.4ps   1.13V      1.248V     1.103V
722.2ps   1.256V     1.248V     1.186V
839.3ps   1.338V     1.248V     1.229V
979.9ps   1.379V     1.25V      1.249V
1.21ns    1.402V     1.282V     1.255V
1.425ns   1.408V     1.47V      1.257V
1.702ns   1.409V     1.536V     1.259V
3.9ns     1.407V     1.56V      1.26V
[Falling Waveform]
R_fixture = 50.000
C_fixture = 3p
V_fixture = 1.2519
V_fixture_min = 1.4025
V_fixture_max = 1.1081
|  time   V(typ)   V(min)   V(max)
0s        1.405V     1.557V     1.259V
312.3ps   1.405V     1.557V     1.26V
421.6ps   1.424V     1.557V     1.315V
523.1ps   1.446V     1.557V     1.208V
780.8ps   1.198V     1.561V     1.021V
976ps     1.133V     1.601V     980.8mV
1.167ns   1.109V     1.511V     969.3mV
1.359ns   1.101V     1.352V     965.1mV
1.632ns   1.098V     1.27V      961.5mV
3.9ns     1.098V     1.247V     958mV
[Ramp]
| variable   typ   min   max
dV/dt_r  0.185257/2.043e-10   0.1869891/2.52e-10   0.1815883/1.69e-10
dV/dt_f  0.1841649/2.40e-10   0.1858596/2.7e-10   0.1803304/2.58e-10
R_load = 50
|   End of [Model]: out3_300mV_2p25v
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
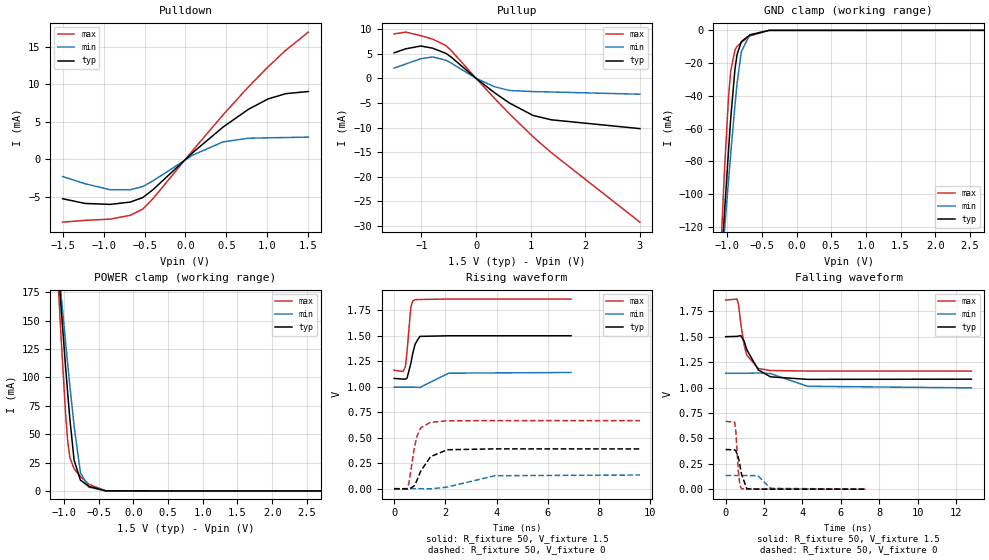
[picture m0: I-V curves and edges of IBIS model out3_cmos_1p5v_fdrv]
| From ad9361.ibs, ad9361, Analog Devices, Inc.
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|   Model: io1_1p5v_fdrv
[Model]   out3_cmos_1p5v_fdrv
Model_type  3-state
Vref=0
Vmeas=0.75
Rref=1G
Cref=3pF
|variable   typ   min   max
C_comp_pullup   5.815188E-13 5.233586E-13 5.940785E-13
C_comp_pulldown   2.205759E-13 2.086364E-13 2.664661E-13
[C Comp Corner]
C_comp_pullup   5.233586E-13 5.815188E-13 5.940785E-13
C_comp_pulldown   2.086364E-13 2.664661E-13 2.205759E-13
[Temperature Range]   25   85   -40
[Voltage Range]   1.5   1.14   1.86
[Power Clamp Reference] 1.5   1.14   1.86
[GND Clamp Reference]   0   0   0
[Pullup Reference]   1.5   1.14   1.86
[Pulldown Reference]   0   0   0
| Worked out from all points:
|   slope of the pulldown table from 0 to 0.225 V, typ, clamps not added: 102 ohm
|   slope of the pullup table from 0 to 0.225 V, typ, clamps not added: 114 ohm
|   GND clamp passes 1 mA (typ) near -0.56 V on its own axis
|   POWER clamp passes 1 mA (typ) near -0.52 V on its own axis
|   rising waveform, R_fixture 50, V_fixture 1.5: 20-80 % time 214ps typ, 487ps min, 140ps max; typ from 1.08 V to 1.5 V
|   falling waveform, R_fixture 50, V_fixture 1.5: 20-80 % time 728ps typ, 1.15ns min, 413ps max; typ from 1.5 V to 1.08 V
|   rising waveform, R_fixture 50, V_fixture 0: 20-80 % time 529ps typ, 1.06ns min, 304ps max; typ from 0 V to 0.39 V
|   falling waveform, R_fixture 50, V_fixture 0: 20-80 % time 246ps typ, 393ps min, 145ps max; typ from 0.39 V to 0 V
[Power clamp]
| Voltage   I(typ)   I(min)   I(max)
-1.5V     564.4mA    490.2mA    687.7mA
-1.102V   210.3mA    211.7mA    200.8mA
-1.071V   184.5mA    191.2mA    165.7mA
-1.041V   159mA      170.9mA    131.6mA
-979.6mV  109.7mA    131.1mA    68.5mA
-949mV    86.25mA    111.8mA    43.96mA
-918.4mV  64.06mA    92.96mA    29.73mA
-857.1mV  27.23mA    57.53mA    19.46mA
-765.3mV  9.518mA    16.04mA    12.73mA
-642.9mV  3.937mA    3.277mA    5.83mA
-398mV    58.18uA    68.43uA    48.25uA
3V        -476.1pA   -8.355nA   -54.5pA
[GND Clamp]
| Voltage   I(typ)   I(min)   I(max)
-1.5V     -445.9mA   -384.7mA   -547.8mA
-1.102V   -154.8mA   -156.9mA   -143.7mA
-1.071V   -133.5mA   -140.1mA   -114.8mA
-1.041V   -112.6mA   -123.4mA   -87mA
-979.6mV  -72.45mA   -90.93mA   -39.82mA
-949mV    -53.65mA   -75.22mA   -24.76mA
-887.8mV  -23.53mA   -45.58mA   -11.88mA
-857.1mV  -14.7mA    -32.12mA   -9.847mA
-795.9mV  -6.885mA   -12.98mA   -7.326mA
-673.5mV  -2.867mA   -2.665mA   -3.445mA
-398mV    -36.1uA    -43.42uA   -23.76uA
3V        1.044nA    1.449nA    41.2pA
[Pullup]
| Voltage   I(typ)   I(min)   I(max)
-1.5V     5.172mA    2.057mA    9mA
-1.286V   5.99mA     2.908mA    9.378mA
-1.01V    6.55mA     3.968mA    8.65mA
-795.9mV  6.117mA    4.337mA    7.962mA
-551mV    5.057mA    3.651mA    6.634mA
-459.2mV  4.342mA    3.119mA    5.685mA
0V        260.8nA    540.6nA    125.1nA
336.7mV   -2.914mA   -1.708mA   -4.047mA
612.2mV   -5.021mA   -2.471mA   -7.22mA
1.041V    -7.528mA   -2.695mA   -11.83mA
1.378V    -8.425mA   -2.773mA   -15.09mA
3V        -10.21mA   -3.23mA    -29.2mA
[Pulldown]
| Voltage   I(typ)   I(min)   I(max)
-1.5V     -5.271mA   -2.307mA   -8.404mA
-1.224V   -5.903mA   -3.272mA   -8.157mA
-918.4mV  -6.027mA   -4.068mA   -7.995mA
-673.5mV  -5.719mA   -4.067mA   -7.483mA
-520.4mV  -5.107mA   -3.65mA    -6.653mA
-398mV    -4.082mA   -2.898mA   -5.286mA
91.84mV   916.9uA    574.5uA    1.22mA
459.2mV   4.302mA    2.32mA     5.941mA
765.3mV   6.653mA    2.803mA    9.632mA
1.01V     8.063mA    2.868mA    12.37mA
1.224V    8.758mA    2.9mA      14.56mA
1.5V      9.049mA    2.956mA    16.98mA
[Rising Waveform]
R_fixture = 50
V_fixture = 1.5
V_fixture_min = 1.14
V_fixture_max = 1.86
| time   V(typ)   V(min)   V(max)
0s        1.082V     996.7mV    1.162V
352ps     1.075V     996.7mV    1.15V
441.4ps   1.075V     996.7mV    1.198V
504.4ps   1.083V     996.8mV    1.342V
651.5ps   1.227V     996.7mV    1.78V
730.6ps   1.329V     996.1mV    1.842V
821.2ps   1.419V     995.5mV    1.854V
1.003ns   1.494V     992.5mV    1.856V
2.129ns   1.5V       1.133V     1.86V
6.908ns   1.5V       1.14V      1.86V
[Falling Waveform]
R_fixture = 50
V_fixture = 1.5
V_fixture_min = 1.14
V_fixture_max = 1.86
| time   V(typ)   V(min)   V(max)
0s        1.5V       1.14V      1.86V
594.7ps   1.503V     1.14V      1.87V
671.1ps   1.506V     1.14V      1.815V
792.9ps   1.51V      1.14V      1.622V
967.9ps   1.455V     1.14V      1.414V
1.103ns   1.372V     1.14V      1.319V
1.703ns   1.173V     1.143V     1.186V
2.34ns    1.105V     1.137V     1.167V
4.266ns   1.08V      1.012V     1.162V
12.81ns   1.082V     996.4mV    1.162V
[Rising Waveform]
R_fixture = 50
V_fixture = 0
V_fixture_min = 0
V_fixture_max = 0
| time   V(typ)   V(min)   V(max)
0s        5.278nV    29.5nV     609.4pV
500.6ps   -2.042mV   1.459uV    -250.4uV
579.5ps   -4.567mV   -3.593uV   53.99mV
788.6ps   28.03mV    -17.04uV   401.5mV
895.2ps   83.61mV    189.1uV    515.3mV
1.039ns   171.9mV    343uV      596.1mV
1.421ns   313.7mV    -2.315mV   651.2mV
2.074ns   382.1mV    16.16mV    665.9mV
3.936ns   390.7mV    127.4mV    667.8mV
9.598ns   390.1mV    134.2mV    667.5mV
[Falling Waveform]
R_fixture = 50
V_fixture = 0
V_fixture_min = 0
V_fixture_max = 0
| time   V(typ)   V(min)   V(max)
0s        390.1mV    134.2mV    667.5mV
471.6ps   386.7mV    134.2mV    657.9mV
526ps     379.7mV    134.2mV    582mV
657.9ps   315.9mV    134.2mV    186.4mV
746.7ps   235.4mV    134.3mV    34.88mV
829.3ps   145.6mV    134.2mV    5.973mV
1.108ns   3.14mV     133.9mV    1.631mV
1.669ns   363.7uV    133mV      608.7uV
2.351ns   208.4uV    8.037mV    242.6uV
7.291ns   -1.756uV   17.25uV    -7.05uV
[Ramp]
| variable   typ   min   max
dV/dt_r  0.234060/5.29e-10   0.080519/1.06e-9   0.400471/3.04e-10
dV/dt_f  0.250811/7.28e-10   0.086041/1.14e-9   0.418548/4.13e-10
R_load = 50
|   End of [Model]: io1_1p5v_fdrv
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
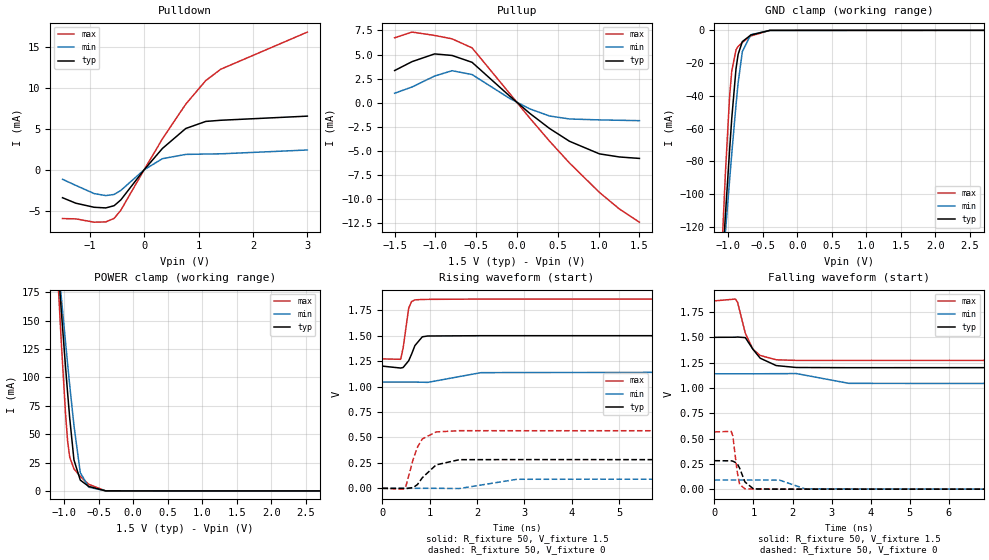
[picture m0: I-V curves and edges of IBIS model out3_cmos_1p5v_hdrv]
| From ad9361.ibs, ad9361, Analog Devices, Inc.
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|   Model: io1_1p5v_hdrv
[Model]   out3_cmos_1p5v_hdrv
Model_type  3-state
Vref=0
Vmeas=0.75
Rref=1G
Cref=3pF
|variable   typ   min   max
C_comp_pullup   5.808326E-13 5.232606E-13 5.940237E-13
C_comp_pulldown   2.205956E-13 2.086723E-13 2.667305E-13
[C Comp Corner]
C_comp_pullup   5.232606E-13 5.808326E-13 5.940237E-13
C_comp_pulldown   2.086723E-13 2.667305E-13 2.205956E-13
[Temperature Range]   25   85   -40
[Voltage Range]   1.5   1.14   1.86
[Power Clamp Reference] 1.5   1.14   1.86
[GND Clamp Reference]   0   0   0
[Pullup Reference]   1.5   1.14   1.86
[Pulldown Reference]   0   0   0
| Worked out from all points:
|   slope of the pulldown table from 0 to 0.225 V, typ, clamps not added: 125 ohm
|   slope of the pullup table from 0 to 0.225 V, typ, clamps not added: 142 ohm
|   GND clamp passes 1 mA (typ) near -0.56 V on its own axis
|   POWER clamp passes 1 mA (typ) near -0.52 V on its own axis
|   rising waveform, R_fixture 50, V_fixture 1.5: 20-80 % time 156ps typ, 352ps min, 105ps max; typ from 1.2 V to 1.5 V
|   falling waveform, R_fixture 50, V_fixture 1.5: 20-80 % time 404ps typ, 616ps min, 318ps max; typ from 1.5 V to 1.2 V
|   rising waveform, R_fixture 50, V_fixture 0: 20-80 % time 347ps typ, 532ps min, 251ps max; typ from 0 V to 0.281 V
|   falling waveform, R_fixture 50, V_fixture 0: 20-80 % time 183ps typ, 307ps min, 115ps max; typ from 0.281 V to 0 V
[Power clamp]
| Voltage   I(typ)   I(min)   I(max)
-1.5V     564.4mA    490.2mA    687.7mA
-1.102V   210.3mA    211.7mA    200.8mA
-1.071V   184.5mA    191.2mA    165.7mA
-1.041V   159mA      170.9mA    131.6mA
-979.6mV  109.7mA    131.1mA    68.5mA
-949mV    86.25mA    111.8mA    43.96mA
-918.4mV  64.06mA    92.96mA    29.73mA
-857.1mV  27.23mA    57.53mA    19.46mA
-765.3mV  9.518mA    16.04mA    12.73mA
-642.9mV  3.937mA    3.277mA    5.83mA
-398mV    58.18uA    68.43uA    48.25uA
3V        -476.1pA   -19.95nA   -54.5pA
[GND Clamp]
| Voltage   I(typ)   I(min)   I(max)
-1.5V     -445.9mA   -384.7mA   -547.8mA
-1.102V   -154.8mA   -156.9mA   -143.7mA
-1.071V   -133.5mA   -140.1mA   -114.8mA
-1.041V   -112.6mA   -123.4mA   -87mA
-979.6mV  -72.45mA   -90.93mA   -39.82mA
-949mV    -53.65mA   -75.22mA   -24.76mA
-887.8mV  -23.53mA   -45.58mA   -11.88mA
-857.1mV  -14.7mA    -32.12mA   -9.847mA
-795.9mV  -6.885mA   -12.98mA   -7.326mA
-673.5mV  -2.867mA   -2.665mA   -3.445mA
-398mV    -36.1uA    -43.42uA   -23.76uA
3V        1.044nA    1.449nA    41.2pA
[Pullup]
| Voltage   I(typ)   I(min)   I(max)
-1.5V     3.332mA    971.1uA    6.736mA
-1.286V   4.259mA    1.62mA     7.331mA
-1.01V    5.062mA    2.761mA    6.985mA
-795.9mV  4.9mA      3.313mA    6.626mA
-551mV    4.189mA    2.916mA    5.692mA
-91.84mV  691.9uA    442uA      966.4uA
153.1mV   -1.099mA   -643.8uA   -1.581mA
398mV     -2.691mA   -1.395mA   -4.006mA
642.9mV   -4.024mA   -1.705mA   -6.283mA
1.01V     -5.334mA   -1.802mA   -9.342mA
1.255V    -5.657mA   -1.84mA    -11.07mA
1.5V      -5.808mA   -1.881mA   -12.44mA
|3.000000   -6.769824E-03   -2.206850E-03   -2.033422E-02
[Pulldown]
| Voltage   I(typ)   I(min)   I(max)
-1.5V     -3.423mA   -1.163mA   -5.975mA
-1.255V   -4.095mA   -1.913mA   -6.015mA
-918.4mV  -4.593mA   -2.915mA   -6.42mA
-704.1mV  -4.672mA   -3.16mA    -6.385mA
-551mV    -4.397mA   -3.021mA   -5.952mA
-428.6mV  -3.691mA   -2.529mA   -4.957mA
0V        -313.8nA   -636.3nA   -151nA
336.7mV   2.616mA    1.362mA    3.79mA
765.3mV   5.06mA     1.884mA    8.043mA
1.133V    5.925mA    1.931mA    10.93mA
1.408V    6.067mA    1.955mA    12.32mA
3V        6.573mA    2.425mA    16.87mA
[Rising Waveform]
R_fixture = 50
V_fixture = 1.5
V_fixture_min = 1.14
V_fixture_max = 1.86
| time   V(typ)   V(min)   V(max)
0s        1.201V     1.044V     1.272V
387.4ps   1.182V     1.044V     1.268V
439.6ps   1.188V     1.044V     1.382V
555.8ps   1.254V     1.044V     1.771V
618.1ps   1.32V      1.044V     1.836V
687.5ps   1.403V     1.044V     1.852V
843.4ps   1.489V     1.043V     1.856V
955.4ps   1.497V     1.041V     1.857V
2.084ns   1.5V       1.137V     1.86V
6.512ns   1.5V       1.14V      1.86V
[Falling Waveform]
R_fixture = 50
V_fixture = 1.5
V_fixture_min = 1.14
V_fixture_max = 1.86
| time   V(typ)   V(min)   V(max)
0s        1.5V       1.14V      1.86V
537.1ps   1.501V     1.14V      1.878V
592ps     1.503V     1.14V      1.847V
791.7ps   1.497V     1.14V      1.539V
987.3ps   1.381V     1.14V      1.382V
1.171ns   1.294V     1.14V      1.321V
1.582ns   1.221V     1.141V     1.278V
2.098ns   1.202V     1.142V     1.272V
3.449ns   1.2V       1.045V     1.272V
10.72ns   1.201V     1.044V     1.272V
[Rising Waveform]
R_fixture = 50
V_fixture = 0
V_fixture_min = 0
V_fixture_max = 0
| time   V(typ)   V(min)   V(max)
0s        5.761nV    31.35nV    566.6pV
441.6ps   -515.2uV   2.363uV    -8.29mV
499.3ps   -2.491mV   1.627uV    24.9mV
653.7ps   8.229mV    -15.85uV   290.6mV
741.4ps   37.69mV    -36.89uV   404.5mV
846.4ps   105.7mV    104.3uV    486.5mV
1.135ns   230.5mV    -78.38uV   554.2mV
1.625ns   281.5mV    -1.933mV   566.4mV
2.843ns   282.4mV    89.01mV    566mV
9.034ns   281.3mV    90.34mV    565.7mV
[Falling Waveform]
R_fixture = 50
V_fixture = 0
V_fixture_min = 0
V_fixture_max = 0
| time   V(typ)   V(min)   V(max)
0s        281.3mV    90.43mV    565.7mV
432ps     279.8mV    90.43mV    570.6mV
471.2ps   276.8mV    90.43mV    524.9mV
580ps     255.1mV    90.43mV    180.5mV
644.8ps   207.6mV    90.43mV    45.91mV
782.2ps   70.92mV    90.44mV    3.326mV
1ns       2.357mV    90.25mV    1.808mV
1.667ns   148.7uV    89.42mV    304.9uV
2.32ns    73.84uV    3.166mV    138.7uV
7.793ns   -2.191uV   11.69uV    -9.492uV
[Ramp]
| variable   typ   min   max
dV/dt_r  0.168774/3.48E-10   0.054213/5.32E-10   0.339449/2.51E-10
dV/dt_f  0.179216/4.04E-10   0.057672/6.16E-10   0.352544/3.18E-10
R_load = 50
|   End of [Model]: io1_1p5v_hdrv
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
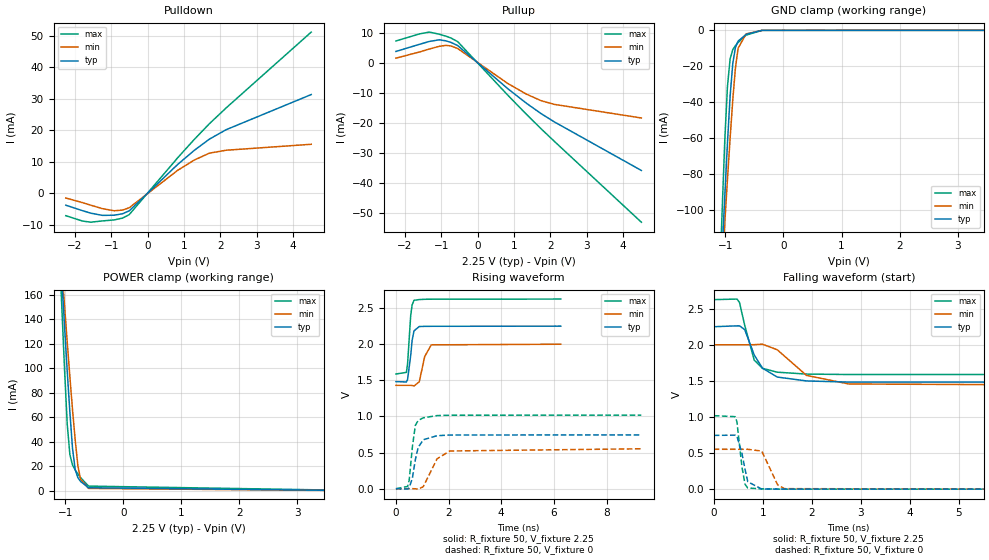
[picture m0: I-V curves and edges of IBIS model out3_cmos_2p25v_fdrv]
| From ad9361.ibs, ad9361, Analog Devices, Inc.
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|   Model: io1_2p25v_fdrv
[Model]   out3_cmos_2p25v_fdrv
Model_type  3-state
Vref=0
Vmeas=1.125
Rref=1G
Cref=3pF
|variable   typ   min   max
C_comp_pullup   6.003834E-13 5.336653E-13 6.165957E-13
C_comp_pulldown   2.095233E-13 1.951056E-13 2.399350E-13
[C Comp Corner]
C_comp_pullup   5.336653E-13 6.165957E-13 6.003834E-13
C_comp_pulldown   1.951056E-13 2.399350E-13 2.095233E-13
[Temperature Range]   25   85   -40
[Voltage Range]   2.25   2   2.625
[Power Clamp Reference]  2.25   2   2.625
[GND Clamp Reference]   0   0   0
[Pullup Reference]   2.25   2   2.625
[Pulldown Reference]   0   0   0
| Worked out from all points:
|   slope of the pulldown table from 0 to 0.337 V, typ, clamps not added: 88 ohm
|   slope of the pullup table from 0 to 0.337 V, typ, clamps not added: 93.9 ohm
|   GND clamp passes 1 mA (typ) near -0.56 V on its own axis
|   POWER clamp passes 1 mA (typ) near -0.52 V on its own axis
|   rising waveform, R_fixture 50, V_fixture 2.25: 20-80 % time 138ps typ, 219ps min, 113ps max; typ from 1.48 V to 2.25 V
|   falling waveform, R_fixture 50, V_fixture 2.25: 20-80 % time 371ps typ, 674ps min, 229ps max; typ from 2.25 V to 1.48 V
|   rising waveform, R_fixture 50, V_fixture 0: 20-80 % time 252ps typ, 492ps min, 180ps max; typ from 0 V to 0.745 V
|   falling waveform, R_fixture 50, V_fixture 0: 20-80 % time 127ps typ, 216ps min, 107ps max; typ from 0.745 V to 0 V
[Power clamp]
| Voltage   I(typ)   I(min)   I(max)
-2.25V    1.271A     1.049A     1.657A
-1.102V   210.4mA    211.8mA    200.9mA
-1.056V   171.8mA    181mA      148.6mA
-1.01V    134.1mA    150.9mA    98.92mA
-964.3mV  97.88mA    121.4mA    54.59mA
-918.4mV  64.07mA    92.95mA    29.61mA
-872.4mV  34.4mA     66mA       21.07mA
-826.5mV  17.26mA    41.41mA    17.11mA
-780.6mV  10.77mA    20.58mA    13.85mA
-734.7mV  7.761mA    9.575mA    10.88mA
-596.9mV  2.59mA     2.056mA    3.923mA
4.5V      -737.4pA   -8.516nA   -142.8pA
[GND Clamp]
| Voltage   I(typ)   I(min)   I(max)
-2.25V    -1.014A    -826.4mA   -1.341A
-1.102V   -154.8mA   -156.9mA   -143.6mA
-1.056V   -123mA     -131.7mA   -100.7mA
-1.01V    -92.17mA   -107mA     -60.93mA
-964.3mV  -62.86mA   -82.98mA   -31.22mA
-918.4mV  -36.52mA   -60mA      -15.86mA
-872.4mV  -18.39mA   -38.62mA   -10.69mA
-826.5mV  -9.489mA   -20.77mA   -8.487mA
-780.6mV  -5.999mA   -10.01mA   -6.763mA
-642.9mV  -2.25mA    -1.993mA   -2.676mA
-367.3mV  -13.87uA   -18.83uA   -7.521uA
4.5V      1.312nA    2.103nA    66.85pA
[Pullup]
| Voltage   I(typ)   I(min)   I(max)
-2.25V    3.851mA    1.611mA    7.34mA
-1.607V   6.212mA    3.658mA    9.69mA
-1.332V   7.182mA    4.662mA    10.31mA
-1.056V   7.739mA    5.563mA    9.593mA
-872.4mV  7.384mA    5.88mA     8.936mA
-734.7mV  6.851mA    5.68mA     8.325mA
-551mV    5.811mA    4.813mA    7.12mA
826.5mV   -8.58mA    -6.839mA   -10.74mA
1.332V    -13.37mA   -10.35mA   -17.03mA
1.745V    -16.92mA   -12.59mA   -21.98mA
2.112V    -19.69mA   -13.82mA   -26.2mA
4.5V      -35.86mA   -18.35mA   -53.12mA
[Pulldown]
| Voltage   I(typ)   I(min)   I(max)
-2.25V    -3.829mA   -1.549mA   -7.157mA
-1.791V   -5.567mA   -3.018mA   -8.856mA
-1.561V   -6.363mA   -3.838mA   -9.223mA
-1.24V    -7.063mA   -4.932mA   -8.817mA
-918.4mV  -7.002mA   -5.597mA   -8.502mA
-688.8mV  -6.544mA   -5.384mA   -7.927mA
-505.1mV  -5.626mA   -4.635mA   -6.816mA
826.5mV   9.098mA    7.231mA    11.21mA
1.286V    13.6mA     10.51mA    17.07mA
1.699V    17.13mA    12.68mA    22.02mA
2.158V    20.12mA    13.61mA    27.02mA
4.5V      31.28mA    15.5mA     51.1mA
[Rising Waveform]
R_fixture = 50
V_fixture = 2.25
V_fixture_min = 2
V_fixture_max = 2.625
| time   V(typ)   V(min)   V(max)
0s        1.482V     1.431V     1.588V
396.8ps   1.478V     1.431V     1.61V
442.7ps   1.512V     1.431V     1.727V
562ps     1.848V     1.431V     2.401V
615.8ps   2.054V     1.429V     2.545V
686.7ps   2.185V     1.422V     2.608V
887.2ps   2.245V     1.48V      2.618V
1.092ns   2.247V     1.829V     2.622V
1.343ns   2.248V     1.991V     2.623V
6.262ns   2.25V      2V         2.625V
[Falling Waveform]
R_fixture = 50
V_fixture = 2.25
V_fixture_min = 2
V_fixture_max = 2.625
| time   V(typ)   V(min)   V(max)
0s        2.25V      2V         2.625V
474.3ps   2.262V     2V         2.633V
525.3ps   2.262V     2V         2.585V
631.6ps   2.21V      2V         2.27V
825.5ps   1.859V     2.001V     1.788V
993.9ps   1.676V     2.008V     1.674V
1.295ns   1.553V     1.931V     1.62V
1.894ns   1.499V     1.575V     1.594V
2.756ns   1.483V     1.457V     1.588V
10.9ns    1.482V     1.431V     1.588V
[Rising Waveform]
R_fixture = 50
V_fixture = 0
V_fixture_min = 0
V_fixture_max = 0
| time   V(typ)   V(min)   V(max)
0s        12.37nV    40.07nV    4.407nV
443.9ps   -5.396mV   -2.511uV   31.17mV
503.3ps   14.08mV    -6.883uV   116.3mV
624.5ps   144.8mV    766.8uV    577mV
739.1ps   405.6mV    -1.172mV   878.7mV
844.4ps   570.3mV    -6.424mV   943.8mV
1.038ns   677.7mV    27.23mV    981.8mV
1.562ns   733.7mV    414.1mV    1.012V
2.046ns   742.9mV    522.1mV    1.017V
9.321ns   745.2mV    552.5mV    1.018V
[Falling Waveform]
R_fixture = 50
V_fixture = 0
V_fixture_min = 0
V_fixture_max = 0
| time   V(typ)   V(min)   V(max)
0s        745.2mV    552.4mV    1.018V
438.3ps   747.9mV    552.4mV    1.004V
473.2ps   731.3mV    552.4mV    931.2mV
574.9ps   497.1mV    552.4mV    308.1mV
639.3ps   271.3mV    552.3mV    66.27mV
694.3ps   102.3mV    552.3mV    16.43mV
979.1ps   2.158mV    527.4mV    3.764mV
1.304ns   903.9uV    59.2mV     1.27mV
1.441ns   728.9uV    7.013mV    962.7uV
7.757ns   -4.189uV   1.193uV    -5.818uV
[Ramp]
| variable   typ   min   max
dV/dt_r  0.447114/2.52E-10   0.331468/4.92E-10   0.610631/1.80E-10
dV/dt_f  0.460652/3.71E-10   0.341249/6.74E-10   0.621941/2.29E-10
R_load = 50
|   End of [Model]: io1_2p25v_fdrv
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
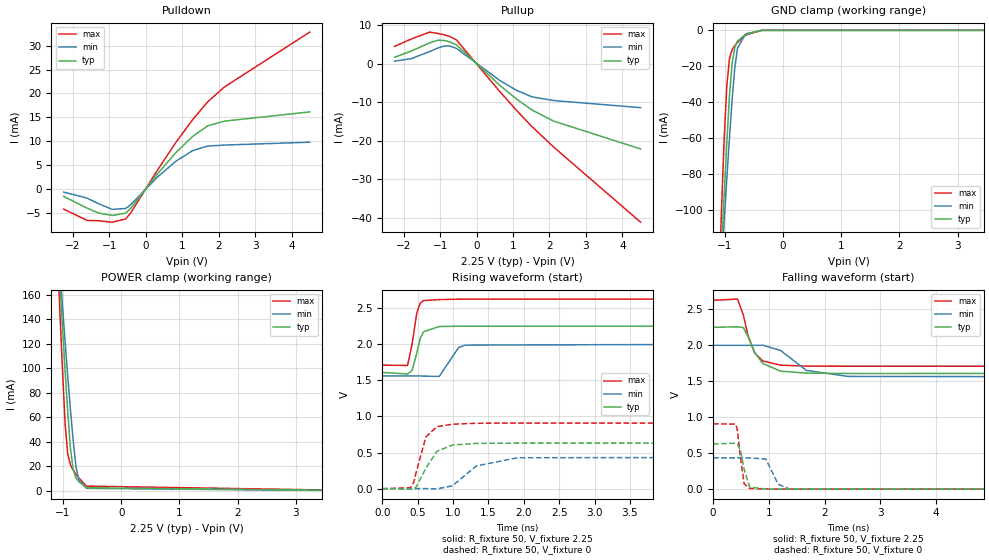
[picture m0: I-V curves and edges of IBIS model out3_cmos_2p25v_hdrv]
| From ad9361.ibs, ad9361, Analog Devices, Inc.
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|   Model: io1_2p25v_hdrv
[Model]   out3_cmos_2p25v_hdrv
Model_type  3-state
Vref=0
Vmeas=1.125
Rref=1G
Cref=3pF
|variable   typ   min   max
C_comp_pullup   6.003470E-13 5.336184E-13 6.163979E-13
C_comp_pulldown   2.095363E-13 1.951223E-13 2.400153E-13
[C Comp Corner]
C_comp_pullup   5.336184E-13 6.163979E-13 6.003470E-13
C_comp_pulldown   1.951223E-13 2.400153E-13 2.095363E-13
[Temperature Range]   25   85   -40
[Voltage Range]   2.25   2   2.625
[Power Clamp Reference]  2.25   2   2.625
[GND Clamp Reference]   0   0   0
[Pullup Reference]   2.25   2   2.625
[Pulldown Reference]   0   0   0
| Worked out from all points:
|   slope of the pulldown table from 0 to 0.337 V, typ, clamps not added: 103 ohm
|   slope of the pullup table from 0 to 0.337 V, typ, clamps not added: 111 ohm
|   GND clamp passes 1 mA (typ) near -0.56 V on its own axis
|   POWER clamp passes 1 mA (typ) near -0.52 V on its own axis
|   rising waveform, R_fixture 50, V_fixture 2.25: 20-80 % time 107ps typ, 163ps min, 85.9ps max; typ from 1.61 V to 2.25 V
|   falling waveform, R_fixture 50, V_fixture 2.25: 20-80 % time 284ps typ, 456ps min, 211ps max; typ from 2.25 V to 1.61 V
|   rising waveform, R_fixture 50, V_fixture 0: 20-80 % time 210ps typ, 373ps min, 156ps max; typ from 0 V to 0.629 V
|   falling waveform, R_fixture 50, V_fixture 0: 20-80 % time 96.4ps typ, 153ps min, 82.1ps max; typ from 0.629 V to 0 V
[Power clamp]
| Voltage   I(typ)   I(min)   I(max)
-2.25V    1.271A     1.049A     1.657A
-1.102V   210.4mA    211.8mA    200.9mA
-1.056V   171.8mA    181mA      148.6mA
-1.01V    134.1mA    150.9mA    98.92mA
-964.3mV  97.88mA    121.4mA    54.59mA
-918.4mV  64.07mA    92.95mA    29.61mA
-872.4mV  34.4mA     66mA       21.07mA
-826.5mV  17.26mA    41.41mA    17.11mA
-780.6mV  10.77mA    20.58mA    13.85mA
-734.7mV  7.761mA    9.575mA    10.88mA
-596.9mV  2.59mA     2.056mA    3.923mA
4.5V      -737.4pA   -8.516nA   -142.8pA
[GND Clamp]
| Voltage   I(typ)   I(min)   I(max)
-2.25V    -1.014A    -826.4mA   -1.341A
-1.102V   -154.8mA   -156.9mA   -143.6mA
-1.056V   -123mA     -131.7mA   -100.7mA
-1.01V    -92.17mA   -107mA     -60.93mA
-964.3mV  -62.86mA   -82.98mA   -31.22mA
-918.4mV  -36.52mA   -60mA      -15.86mA
-872.4mV  -18.39mA   -38.62mA   -10.69mA
-826.5mV  -9.489mA   -20.77mA   -8.487mA
-780.6mV  -5.999mA   -10.01mA   -6.763mA
-642.9mV  -2.25mA    -1.993mA   -2.676mA
-367.3mV  -13.87uA   -18.83uA   -7.521uA
4.5V      1.312nA    2.103nA    66.85pA
[Pullup]
| Voltage   I(typ)   I(min)   I(max)
-2.25V    1.71mA     704uA      4.54mA
-1.791V   3.338mA    1.361mA    6.471mA
-1.286V   5.477mA    3.21mA     8.266mA
-1.056V   6.163mA    4.149mA    7.897mA
-872.4mV  6.058mA    4.675mA    7.523mA
-734.7mV  5.722mA    4.648mA    7.129mA
-551mV    4.952mA    4.024mA    6.218mA
642.9mV   -5.62mA    -4.364mA   -7.259mA
1.102V    -9.188mA   -6.898mA   -12.14mA
1.515V    -11.96mA   -8.554mA   -16.26mA
2.112V    -14.87mA   -9.53mA    -21.6mA
4.5V      -22.12mA   -11.38mA   -41.16mA
[Pulldown]
| Voltage   I(typ)   I(min)   I(max)
-2.25V    -1.575mA   -674uA     -4.242mA
-1.607V   -4.051mA   -1.948mA   -6.618mA
-1.286V   -5.075mA   -3.139mA   -6.684mA
-918.4mV  -5.573mA   -4.297mA   -6.982mA
-551mV    -5.086mA   -4.099mA   -6.315mA
-413.3mV  -4.115mA   -3.323mA   -5.067mA
321.4mV   3.135mA    2.464mA    3.921mA
826.5mV   7.596mA    5.793mA    9.726mA
1.286V    10.98mA    8.012mA    14.5mA
1.699V    13.2mA     8.971mA    18.22mA
2.158V    14.19mA    9.177mA    21.35mA
4.5V      16.13mA    9.778mA    32.85mA
[Rising Waveform]
R_fixture = 50
V_fixture = 2.25
V_fixture_min = 2
V_fixture_max = 2.625
| time   V(typ)   V(min)   V(max)
0s        1.61V      1.56V      1.71V
358ps     1.588V     1.56V      1.706V
421.7ps   1.637V     1.561V     2V
487.7ps   1.874V     1.561V     2.431V
535.2ps   2.077V     1.561V     2.565V
583.3ps   2.172V     1.558V     2.604V
805.8ps   2.245V     1.554V     2.618V
1.08ns    2.249V     1.955V     2.623V
1.174ns   2.249V     1.988V     2.624V
5.858ns   2.25V      2V         2.625V
[Falling Waveform]
R_fixture = 50
V_fixture = 2.25
V_fixture_min = 2
V_fixture_max = 2.625
| time   V(typ)   V(min)   V(max)
0s        2.25V      2V         2.625V
438.3ps   2.257V     2V         2.643V
543.7ps   2.246V     2V         2.42V
626.1ps   2.122V     2V         2.135V
747.3ps   1.897V     2V         1.894V
892.2ps   1.747V     2.001V     1.781V
1.21ns    1.641V     1.929V     1.724V
1.674ns   1.613V     1.651V     1.711V
2.427ns   1.608V     1.567V     1.709V
12.05ns   1.61V      1.56V      1.71V
[Rising Waveform]
R_fixture = 50
V_fixture = 0
V_fixture_min = 0
V_fixture_max = 0
| time   V(typ)   V(min)   V(max)
0s        13.81nV    40.2nV     4.826nV
398.1ps   -7.008mV   1.002uV    13.15mV
444.3ps   1.955mV    -3.024uV   86.28mV
476.4ps   17.27mV    -5.823uV   215.2mV
616.6ps   283.4mV    790.7uV    716.2mV
771.3ps   516.3mV    -3.846mV   858.1mV
991.9ps   604.4mV    39.8mV     892.4mV
1.329ns   626.3mV    314.5mV    905.2mV
1.912ns   630.4mV    428.1mV    908.5mV
8.682ns   629.3mV    435mV      907.8mV
[Falling Waveform]
R_fixture = 50
V_fixture = 0
V_fixture_min = 0
V_fixture_max = 0
| time   V(typ)   V(min)   V(max)
0s        629.3mV    435mV      907.8mV
406.4ps   638.6mV    435mV      904.5mV
436.8ps   626.8mV    435mV      817.9mV
491.9ps   535.8mV    435mV      434.5mV
557.2ps   278.2mV    435mV      76.18mV
654.6ps   28.91mV    434.8mV    9.626mV
946.7ps   1.984mV    419mV      2.924mV
1.167ns   830.3uV    68.38mV    1.025mV
1.369ns   437.7uV    2.687mV    585uV
8.887ns   -5.948uV   -1.646uV   -5.683uV
[Ramp]
| variable   typ   min   max
dV/dt_r  0.377591/2.10E-10   0.261009/3.73E-10   0.544697/1.56E-10
dV/dt_f  0.384207/2.84E-10   0.263717/4.56E-10   0.549279/2.11E-10
R_load = 50
|   End of [Model]: io1_2p25v_hdrv
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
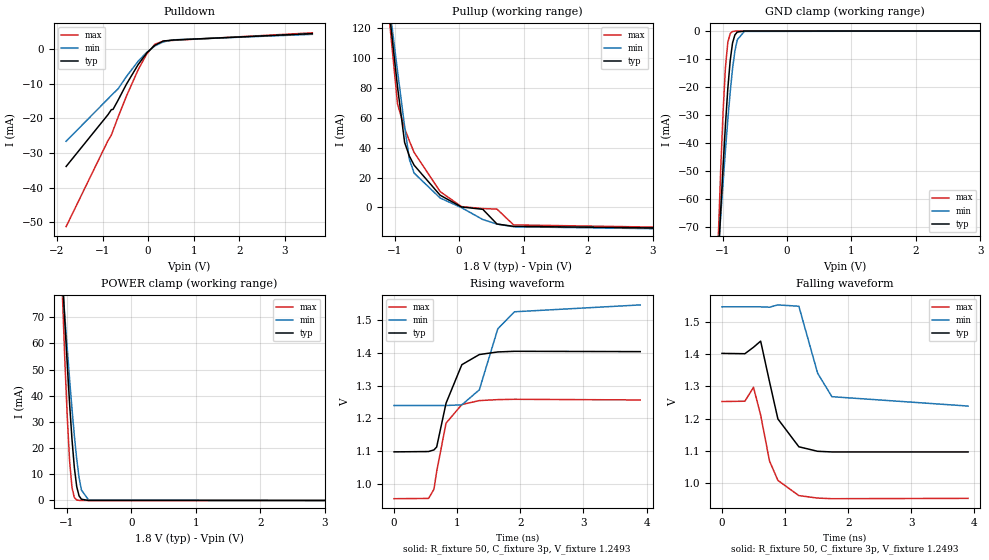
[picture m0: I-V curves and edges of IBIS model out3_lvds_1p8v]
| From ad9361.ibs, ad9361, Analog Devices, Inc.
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|   Model: out3_1p8v
[Model]   out3_lvds_1p8v
Model_type  3-state
Vref=1.2493
Vmeas=1.2493
Rref=50
Cref=3pF
|variable   typ   min   max
C_comp_pullup   1.583470E-13 1.396917E-13 2.122628E-13
C_comp_pulldown   1.253941E-13 0.985981E-13 1.262128E-13
[C Comp Corner]
C_comp_pullup   1.583470E-13 1.396917E-13 2.122628E-13
C_comp_pulldown   1.253941E-13 0.985981E-13 1.262128E-13
[Temperature Range]   25   85   -40
[Voltage Range]   1.8   1.71   1.89
[Power Clamp Reference] 1.8   1.71   1.89
[GND Clamp Reference]   0   0   0
[Pullup Reference]   1.8   1.71   1.89
[Pulldown Reference]   0   0   0
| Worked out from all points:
|   slope of the pulldown table from 0 to 0.27 V, typ, clamps not added: 99.5 ohm
|   slope of the pullup table from 0 to 0.27 V, typ, clamps not added: 158 ohm
|   GND clamp passes 1 mA (typ) near -0.79 V on its own axis
|   POWER clamp passes 1 mA (typ) near -0.79 V on its own axis
|   rising waveform, R_fixture 50, C_fixture 3p, V_fixture 1.2493: 20-80 % time 239ps typ, 315ps min, 193ps max; typ from 1.1 V to 1.4 V
|   falling waveform, R_fixture 50, C_fixture 3p, V_fixture 1.2493: 20-80 % time 249ps typ, 299ps min, 247ps max; typ from 1.4 V to 1.1 V
[Power clamp]
| Voltage   I(typ)   I(min)   I(max)
-1.8V     461.8mA    356.7mA    643.2mA
-1.065V   85.08mA    82.79mA    77.32mA
-1.029V   68.19mA    70.22mA    53.44mA
-991.8mV  52.01mA    57.98mA    32.03mA
-955.1mV  36.88mA    46.19mA    15.03mA
-918.4mV  23.4mA     35.02mA    4.924mA
-881.6mV  12.5mA     24.73mA    1.129mA
-844.9mV  5.274mA    15.76mA    203.9uA
-808.2mV  1.74mA     8.682mA    33.81uA
-771.4mV  479.6uA    3.987mA    5.505uA
-661.2mV  7.202uA    164uA      23.49nA
3.6V      -7.2pA     -7.268pA   -7.2pA
[GND Clamp]
| Voltage   I(typ)   I(min)   I(max)
-1.8V     -456.4mA   -351.6mA   -637.4mA
-1.065V   -80.75mA   -78.6mA    -73mA
-1.029V   -64.07mA   -66.17mA   -49.56mA
-991.8mV  -48.17mA   -54.1mA    -28.85mA
-955.1mV  -33.46mA   -42.53mA   -12.95mA
-918.4mV  -20.57mA   -31.66mA   -4.057mA
-881.6mV  -10.53mA   -21.8mA    -911.3uA
-844.9mV  -4.247mA   -13.4mA    -166.7uA
-808.2mV  -1.364mA   -7.061mA   -28.51uA
-771.4mV  -375.4uA   -3.108mA   -4.808uA
-661.2mV  -6.051uA   -125.9uA   -22.83nA
3.6V      7.2pA      7.279pA    7.2pA
[Pullup]
| Voltage   I(typ)   I(min)   I(max)
-1.8V     434.9mA    404.2mA    483.4mA
-1.102V   138.5mA    142.1mA    134.8mA
-955.1mV  80.61mA    91.26mA    69.19mA
-844.9mV  43.43mA    54.11mA    52.97mA
-771.4mV  34.35mA    32.14mA    44.5mA
-698mV    28.25mA    22.98mA    36.81mA
-293.9mV  8.122mA    6.249mA    10.56mA
36.73mV   279.9uA    -178.4uA   519.2uA
367.3mV   -1.292mA   -8.136mA   -803.3uA
587.8mV   -11.15mA   -11.17mA   -1.168mA
844.9mV   -12.7mA    -12.99mA   -11.73mA
3.6V      -14.07mA   -14.61mA   -13.6mA
[Pulldown]
| Voltage   I(typ)   I(min)   I(max)
-1.8V     -33.9mA    -26.63mA   -51.28mA
-881.6mV  -18.93mA   -14.36mA   -26.43mA
-808.2mV  -17.49mA   -13.37mA   -24.82mA
-771.4mV  -17.42mA   -12.88mA   -23.53mA
-661.2mV  -14.77mA   -11.5mA    -19.66mA
-477.6mV  -10.14mA   -7.915mA   -13.59mA
-220.4mV  -4.474mA   -3.503mA   -5.967mA
-36.73mV  -1.197mA   -971.1uA   -1.505mA
146.9mV   1.128mA    904.9uA    1.413mA
330.6mV   2.335mA    2.099mA    2.338mA
551mV     2.634mA    2.681mA    2.535mA
3.6V      4.479mA    4.281mA    4.714mA
[Rising Waveform]
R_fixture = 50
C_fixture = 3p
V_fixture = 1.2493
V_fixture_min = 1.3925
V_fixture_max = 1.1034
| time   V(typ)   V(min)   V(max)
0s        1.097V     1.239V     953.6mV
546.5ps   1.098V     1.239V     954.4mV
632.4ps   1.103V     1.239V     982.7mV
675.4ps   1.112V     1.239V     1.037V
823.7ps   1.246V     1.239V     1.185V
1.074ns   1.364V     1.241V     1.242V
1.351ns   1.395V     1.287V     1.254V
1.644ns   1.403V     1.474V     1.257V
1.909ns   1.405V     1.526V     1.258V
3.9ns     1.404V     1.547V     1.256V
[Falling Waveform]
R_fixture = 50
C_fixture = 3p
V_fixture = 1.2493
V_fixture_min = 1.3925
V_fixture_max = 1.1034
| time   V(typ)   V(min)   V(max)
0s        1.402V     1.546V     1.253V
363.1ps   1.401V     1.546V     1.254V
499.7ps   1.421V     1.546V     1.297V
612.9ps   1.44V      1.546V     1.211V
753.5ps   1.314V     1.545V     1.069V
886.2ps   1.199V     1.552V     1.009V
1.218ns   1.113V     1.548V     961.9mV
1.515ns   1.099V     1.341V     954.2mV
1.741ns   1.097V     1.268V     952.3mV
3.9ns     1.097V     1.239V     953.3mV
[Ramp]
| variable   typ   min   max
dV/dt_r  0.1841102/2.39e-10   0.1844394/3.15e-10   0.181415/1.93e-10
dV/dt_f  0.1829462/2.49e-10   0.1840748/2.99e-10   0.1799907/2.47e-10
R_load = 50
|   End of [Model]: out3_300mV_1p8v
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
